FUNCTION "FC_GRP_84" : VOID
TITLE =GROUP =84
{ S7_language := '9(1) Angielski (Stany Zjednoczone)  11.01.2022  09:45:15' }
VERSION : 0.1


VAR_TEMP
  CL : "UDT_CABINET";	//CABINET LOCAL
  CR : "UDT_CABINET";	//CABINET REMOTE
  RelError : BOOL ;	//ERROR RELEASE
  RelErrorCL : BOOL ;	//ERROR RELEASE FROM CABINET LOCAL
  RelErrorCR : BOOL ;	//ERROR RELEASE FROM CABINET REMOTE
  RelControl : BOOL ;	//CONTROL RELEASE
  RelControlCL : BOOL ;	//CONTROL RELEASE FROM CABINET LOCAL
  RelControlCR : BOOL ;	//CONTROL RELEASE FROM CABINET REMOTE
  ErrorConfirm : BOOL ;	//ERROR CONFIRM
  AutoOn : BOOL ;	//AUTOMATIC ON
  AutoOff : BOOL ;	//AUTOMATIC OFF
  LAMP_ON : BOOL ;
  FLOW_METER_PE : BOOL ;
  Value_Offset : REAL ;	//VALUE OFFSET
END_VAR
BEGIN
NETWORK
TITLE =GLOBAL SIGNALS

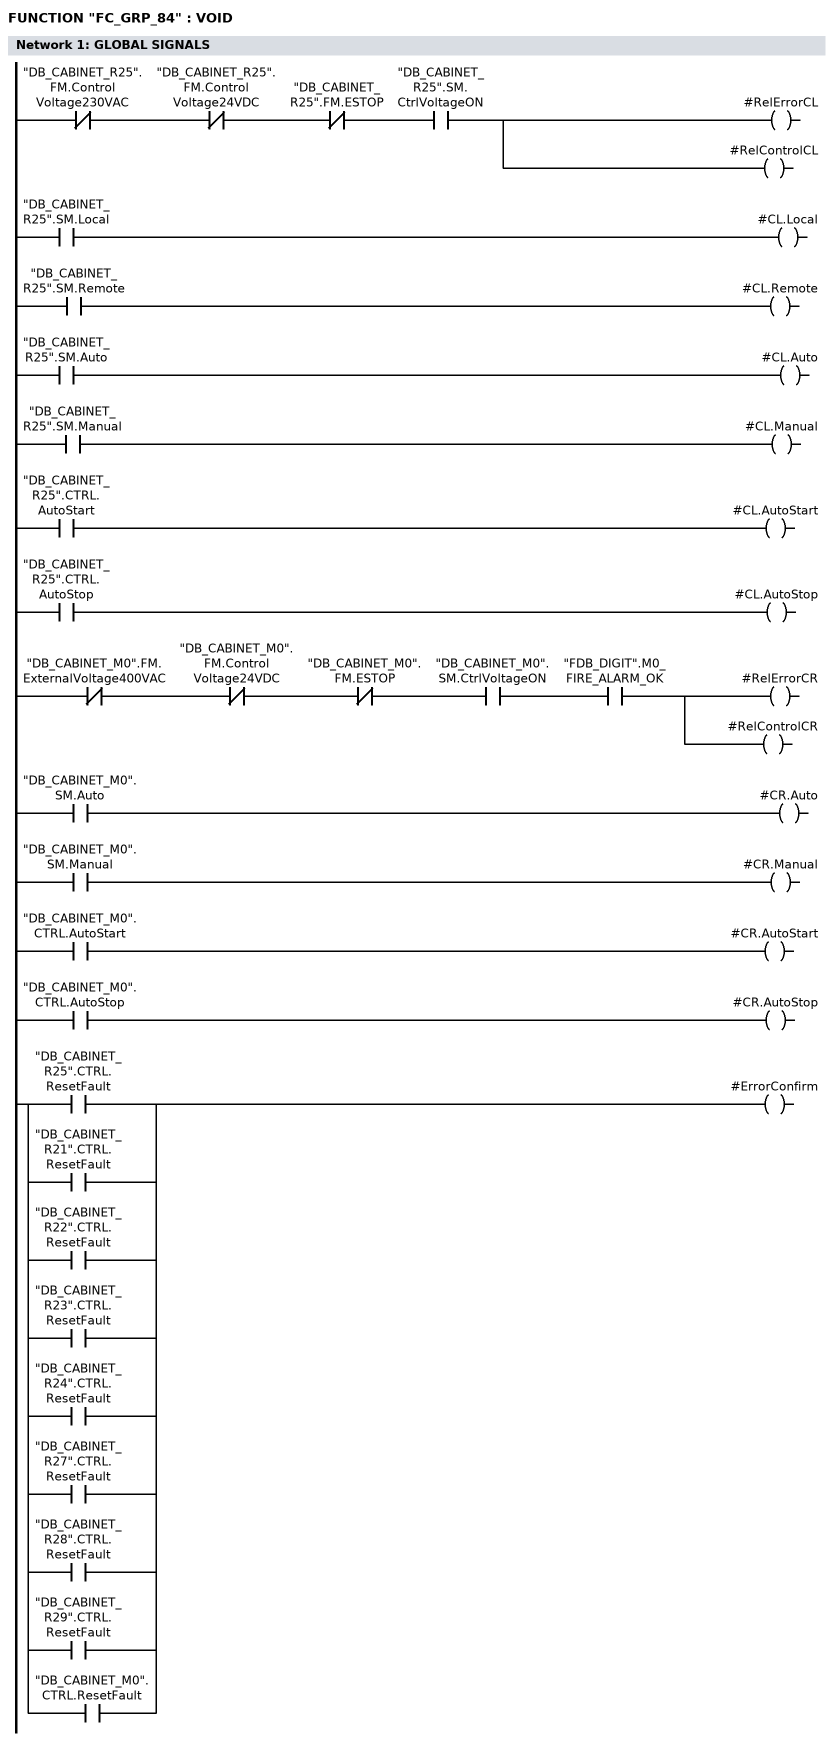
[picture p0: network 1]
// LOCAL
      UN    "DB_CABINET_R25".FM.ControlVoltage230VAC;
      UN    "DB_CABINET_R25".FM.ControlVoltage24VDC;
//      UN    "DB_CABINET_R25".FM.ControlVoltage230VAC_MS
      UN    "DB_CABINET_R25".FM.ESTOP;
      U     "DB_CABINET_R25".SM.CtrlVoltageON;
      =     #RelErrorCL;
      =     #RelControlCL;

      U     "DB_CABINET_R25".SM.Local;
      =     #CL.Local;
      U     "DB_CABINET_R25".SM.Remote;
      =     #CL.Remote;
      U     "DB_CABINET_R25".SM.Auto;
      =     #CL.Auto;
      U     "DB_CABINET_R25".SM.Manual;
      =     #CL.Manual;
      U     "DB_CABINET_R25".CTRL.AutoStart;
      =     #CL.AutoStart;
      U     "DB_CABINET_R25".CTRL.AutoStop;
      =     #CL.AutoStop;

// REMOTE
      UN    "DB_CABINET_M0".FM.ExternalVoltage400VAC;
      UN    "DB_CABINET_M0".FM.ControlVoltage24VDC;
//      UN    "DB_CABINET_M0".FM.ControlVoltage230VAC_MS
      UN    "DB_CABINET_M0".FM.ESTOP;
      U     "DB_CABINET_M0".SM.CtrlVoltageON;
      U     "FDB_DIGIT".M0_FIRE_ALARM_OK;
      =     #RelErrorCR;
      =     #RelControlCR;

      U     "DB_CABINET_M0".SM.Auto;
      =     #CR.Auto;
      U     "DB_CABINET_M0".SM.Manual;
      =     #CR.Manual;
      U     "DB_CABINET_M0".CTRL.AutoStart;
      =     #CR.AutoStart;
      U     "DB_CABINET_M0".CTRL.AutoStop;
      =     #CR.AutoStop;

      U     "DB_CABINET_R25".CTRL.ResetFault;
      O     "DB_CABINET_R21".CTRL.ResetFault;
      O     "DB_CABINET_R22".CTRL.ResetFault;
      O     "DB_CABINET_R23".CTRL.ResetFault;
      O     "DB_CABINET_R24".CTRL.ResetFault;
      O     "DB_CABINET_R27".CTRL.ResetFault;
      O     "DB_CABINET_R28".CTRL.ResetFault;
      O     "DB_CABINET_R29".CTRL.ResetFault;
      O     "DB_CABINET_M0".CTRL.ResetFault;
      =     #ErrorConfirm;

NETWORK
TITLE ==84DOO07-S1F ACCESS DOOR ERROR

      U(    ;
      U(    ;
      O     #ErrorConfirm;
      O     "R25-84DOO07+07TG1-S1:14";
      )     ;
      R     "DB_DIGIT".FM.G84_DOO07;
      U     "FDB_DIGIT".R25_84DOO07_OK;
      =     "DB_DIGIT".SM.G84_DOO07;
      U     "DB_DIGIT".SM.G84_DOO07;
      NOT   ;
      U     #RelErrorCL;
      U     #RelErrorCR;
      S     "DB_DIGIT".FM.G84_DOO07;
      U     "DB_DIGIT".FM.G84_DOO07;
      )     ;
      U     "DURATION_1";
      =     "R25-84DOO07+07TG1-H1:x1";
NETWORK
TITLE ==84FLA11-M1 RELEASE CONTROL/ERROR

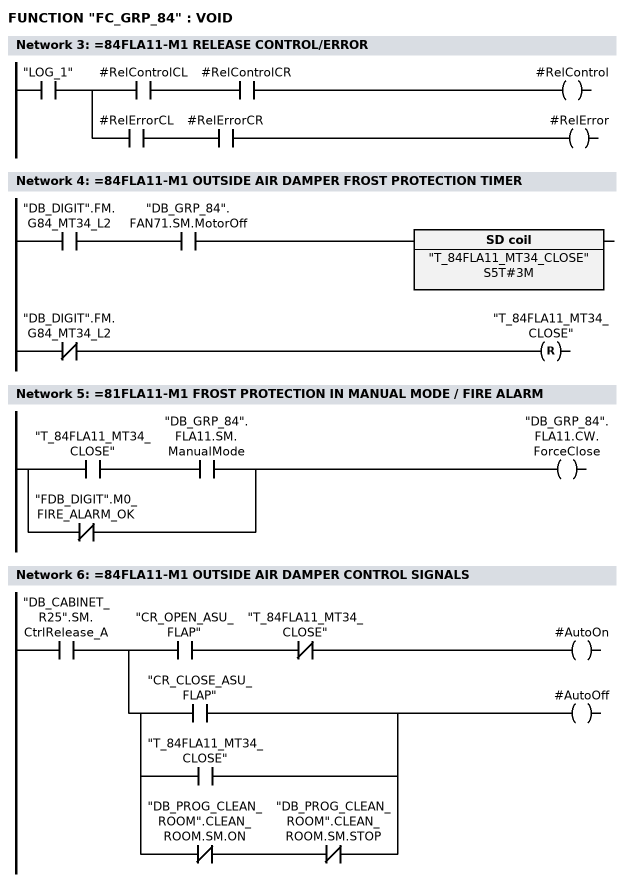
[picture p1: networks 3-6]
      U     "LOG_1";
      =     L     10.0;
      U     L     10.0;
      U     #RelControlCL;
      U     #RelControlCR;
      =     #RelControl;
      U     L     10.0;
      U     #RelErrorCL;
      U     #RelErrorCR;
      =     #RelError;
NETWORK
TITLE ==84FLA11-M1 OUTSIDE AIR DAMPER FROST PROTECTION TIMER

      U     "DB_DIGIT".FM.G84_MT34_L2;
      U     "DB_GRP_84".FAN71.SM.MotorOff;
      L     S5T#3M;
      SE    "T_84FLA11_MT34_CLOSE";
      UN    "DB_DIGIT".FM.G84_MT34_L2;
      R     "T_84FLA11_MT34_CLOSE";
      NOP   0;
      NOP   0;
      NOP   0;
NETWORK
TITLE ==81FLA11-M1 FROST PROTECTION IN MANUAL MODE / FIRE ALARM

      U     "T_84FLA11_MT34_CLOSE";
      U     "DB_GRP_84".FLA11.SM.ManualMode;
      ON    "FDB_DIGIT".M0_FIRE_ALARM_OK;
      =     "DB_GRP_84".FLA11.CW.ForceClose;
NETWORK
TITLE ==84FLA11-M1 OUTSIDE AIR DAMPER CONTROL SIGNALS

      U     "DB_CABINET_R25".SM.CtrlRelease_A;
      =     L     10.0;
      U     L     10.0;
      U     "CR_OPEN_ASU_FLAP";
      UN    "T_84FLA11_MT34_CLOSE";
      =     #AutoOn;
      U     L     10.0;
      U(    ;
      O     "CR_CLOSE_ASU_FLAP";
      O     "T_84FLA11_MT34_CLOSE";
      O     ;
      UN    "DB_PROG_CLEAN_ROOM".CLEAN_ROOM.SM.ON;
      UN    "DB_PROG_CLEAN_ROOM".CLEAN_ROOM.SM.STOP;
      )     ;
      =     #AutoOff;
NETWORK
TITLE ==84FLA11-M1 OUTSIDE AIR DAMPER

      U     #RelControl;
      =     L     10.0;
      BLD   103;
      U     #RelError;
      =     L     10.1;
      BLD   103;
      U     #AutoOn;
      =     L     10.2;
      BLD   103;
      U     #AutoOff;
      =     L     10.3;
      BLD   103;
      U     "LOG_1";
      =     L     10.4;
      BLD   103;
      U(    ;
      U     "R25-84FLA11+X-S1c:4";
      L     S5T#10S;
      SE    "T_84FLA11_LS_O";
      NOP   0;
      NOP   0;
      NOP   0;
      U     "T_84FLA11_LS_O";
      )     ;
      =     L     10.5;
      BLD   103;
      U(    ;
      U     "R25-84FLA11+X-S2c:4";
      L     S5T#10S;
      SE    "T_84FLA11_LS_C";
      NOP   0;
      NOP   0;
      NOP   0;
      U     "T_84FLA11_LS_C";
      )     ;
      =     L     10.6;
      BLD   103;
      U     #ErrorConfirm;
      =     L     10.7;
      BLD   103;
      CALL "FC_FLAP" (
           REL_CONTROL              := L     10.0,
           REL_ERROR                := L     10.1,
           CL                       := #CL,
           CR                       := #CR,
           AUTO_OPEN                := L     10.2,
           AUTO_CLOSE               := L     10.3,
           FUSE                     := L     10.4,
           LS_OPEN                  := L     10.5,
           LS_CLOSE                 := L     10.6,
           ERROR_CONFIRM            := L     10.7,
           MAX_RUNTIME              := 280,
           OPEN                     := "R25-84FLA11+X-M1:2",
           CLOSE                    := "R25-84FLA11+X-M1:3",
           DDB                      := "DB_GRP_84".FLA11);
      NOP   0;
NETWORK
TITLE ==84FTR20-B33 FILTER PRESSURE MONITORING

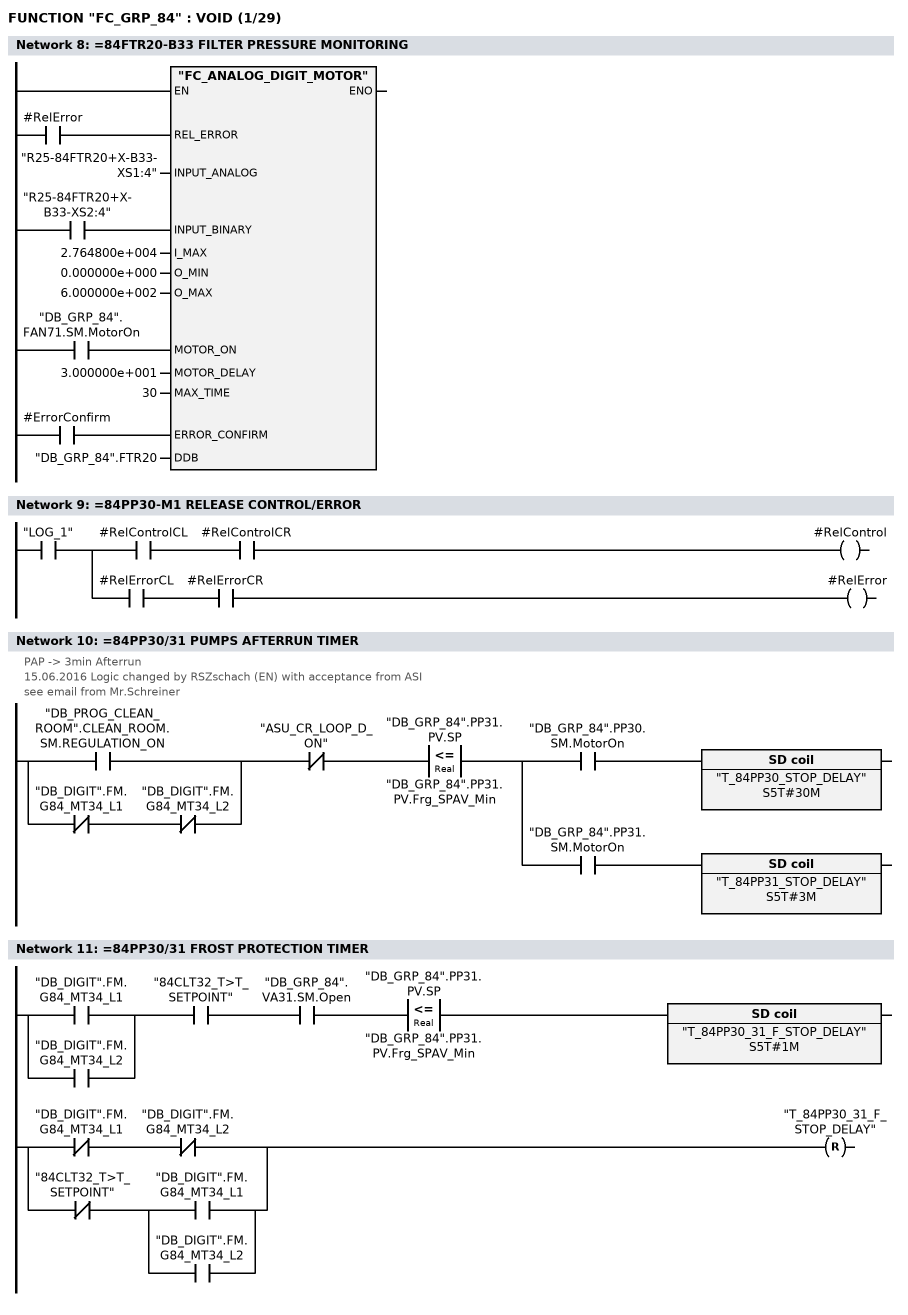
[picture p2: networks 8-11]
      U     #RelError;
      =     L     10.0;
      BLD   103;
      U     "R25-84FTR20+X-B33-XS2:4";
      =     L     10.1;
      BLD   103;
      U     "DB_GRP_84".FAN71.SM.MotorOn;
      =     L     10.2;
      BLD   103;
      U     #ErrorConfirm;
      =     L     10.3;
      BLD   103;
      CALL "FC_ANALOG_DIGIT_MOTOR" (
           REL_ERROR                := L     10.0,
           INPUT_ANALOG             := "R25-84FTR20+X-B33-XS1:4",
           INPUT_BINARY             := L     10.1,
           I_MAX                    := 2.764800e+004,
           O_MIN                    := 0.000000e+000,
           O_MAX                    := 6.000000e+002,
           MOTOR_ON                 := L     10.2,
           MOTOR_DELAY              := 3.000000e+001,
           MAX_TIME                 := 30,
           ERROR_CONFIRM            := L     10.3,
           DDB                      := "DB_GRP_84".FTR20);
      NOP   0;
NETWORK
TITLE ==84PP30-M1 RELEASE CONTROL/ERROR

      U     "LOG_1";
      =     L     10.0;
      U     L     10.0;
      U     #RelControlCL;
      U     #RelControlCR;
      =     #RelControl;
      U     L     10.0;
      U     #RelErrorCL;
      U     #RelErrorCR;
      =     #RelError;
NETWORK
TITLE ==84PP30/31 PUMPS AFTERRUN TIMER
//PAP -> 3min Afterrun
//
//15.06.2016 Logic changed by RSZschach (EN) with acceptance from ASI
//see email from Mr.Schreiner
      U(    ;
      O     "DB_PROG_CLEAN_ROOM".CLEAN_ROOM.SM.REGULATION_ON;
      O     ;
      UN    "DB_DIGIT".FM.G84_MT34_L1;
      UN    "DB_DIGIT".FM.G84_MT34_L2;
      )     ;
      UN    "ASU_CR_LOOP_D_ON";
      U(    ;
      L     "DB_GRP_84".PP31.PV.SP;
      L     "DB_GRP_84".PP31.PV.Frg_SPAV_Min;
      <=R   ;
      )     ;
      =     L     10.0;
      U     L     10.0;
      U     "DB_GRP_84".PP30.SM.MotorOn;
      L     S5T#30M;
      SE    "T_84PP30_STOP_DELAY";
      NOP   0;
      NOP   0;
      NOP   0;
      NOP   0;
      U     L     10.0;
      U     "DB_GRP_84".PP31.SM.MotorOn;
      L     S5T#3M;
      SE    "T_84PP31_STOP_DELAY";
      NOP   0;
      NOP   0;
      NOP   0;
      NOP   0;
NETWORK
TITLE ==84PP30/31 FROST PROTECTION TIMER

      U(    ;
      O     "DB_DIGIT".FM.G84_MT34_L1;
      O     "DB_DIGIT".FM.G84_MT34_L2;
      )     ;
      U     "84CLT32_T>T_SETPOINT";
      U     "DB_GRP_84".VA31.SM.Open;
      U(    ;
      L     "DB_GRP_84".PP31.PV.SP;
      L     "DB_GRP_84".PP31.PV.Frg_SPAV_Min;
      <=R   ;
      )     ;
      L     S5T#1M;
      SE    "T_84PP30_31_F_STOP_DELAY";
      U(    ;
      UN    "DB_DIGIT".FM.G84_MT34_L1;
      UN    "DB_DIGIT".FM.G84_MT34_L2;
      O     ;
      UN    "84CLT32_T>T_SETPOINT";
      U(    ;
      O     "DB_DIGIT".FM.G84_MT34_L1;
      O     "DB_DIGIT".FM.G84_MT34_L2;
      )     ;
      )     ;
      R     "T_84PP30_31_F_STOP_DELAY";
      NOP   0;
      NOP   0;
      NOP   0;
NETWORK
TITLE ==84PP30-M1 PREHEATING CIRCULATION PUMP CONTROL SIGNALS

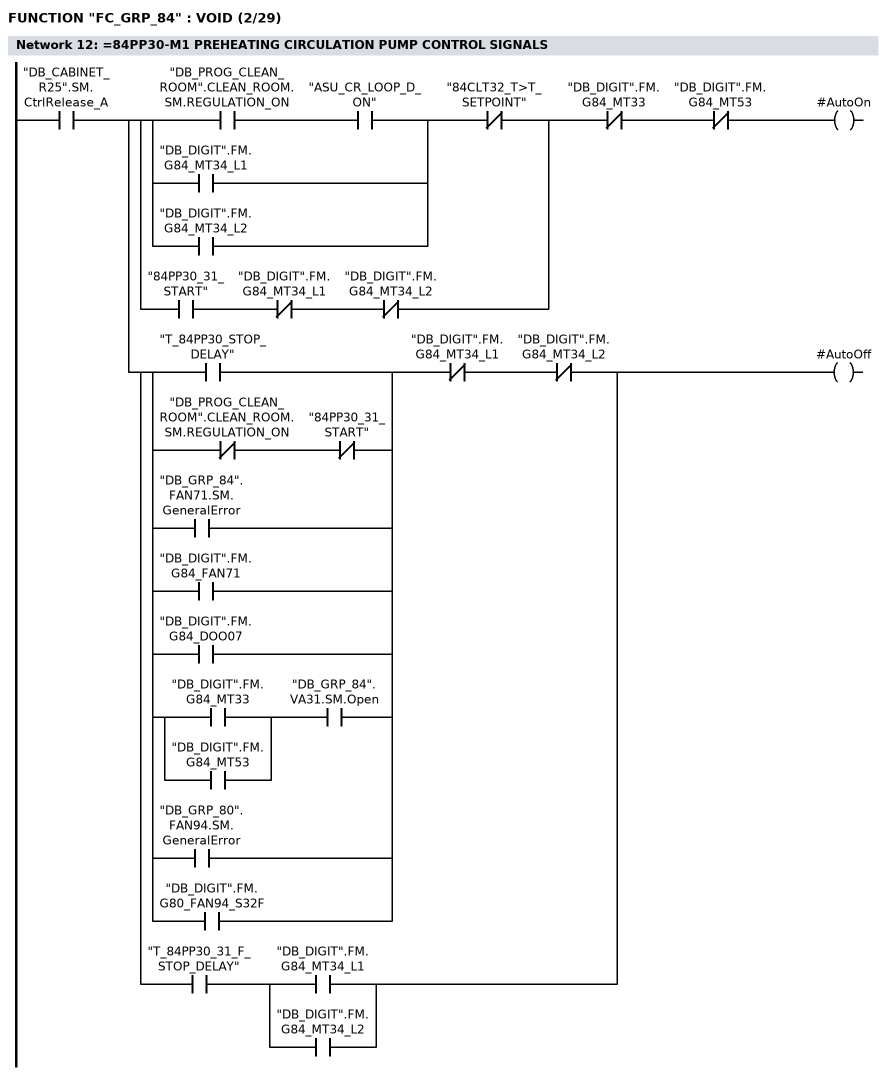
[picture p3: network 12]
      U     "DB_CABINET_R25".SM.CtrlRelease_A;
      =     L     10.0;
      U     L     10.0;
      U(    ;
      U(    ;
      U     "DB_PROG_CLEAN_ROOM".CLEAN_ROOM.SM.REGULATION_ON;
      U     "ASU_CR_LOOP_D_ON";
      O     "DB_DIGIT".FM.G84_MT34_L1;
      O     "DB_DIGIT".FM.G84_MT34_L2;
      )     ;
      UN    "84CLT32_T>T_SETPOINT";
      O     ;
      U     "84PP30_31_START";
      UN    "DB_DIGIT".FM.G84_MT34_L1;
      UN    "DB_DIGIT".FM.G84_MT34_L2;
      )     ;
      UN    "DB_DIGIT".FM.G84_MT33;
      UN    "DB_DIGIT".FM.G84_MT53;
      =     #AutoOn;
      U     L     10.0;
      U(    ;
      U(    ;
      O     "T_84PP30_STOP_DELAY";
      O     ;
      UN    "DB_PROG_CLEAN_ROOM".CLEAN_ROOM.SM.REGULATION_ON;
      UN    "84PP30_31_START";
      O     "DB_GRP_84".FAN71.SM.GeneralError;
      O     "DB_DIGIT".FM.G84_FAN71;
      O     "DB_DIGIT".FM.G84_DOO07;
      O     ;
      U(    ;
      O     "DB_DIGIT".FM.G84_MT33;
      O     "DB_DIGIT".FM.G84_MT53;
      )     ;
      U     "DB_GRP_84".VA31.SM.Open;
      O     "DB_GRP_80".FAN94.SM.GeneralError;
      O     "DB_DIGIT".FM.G80_FAN94_S32F;
      )     ;
      UN    "DB_DIGIT".FM.G84_MT34_L1;
      UN    "DB_DIGIT".FM.G84_MT34_L2;
      O     ;
      U     "T_84PP30_31_F_STOP_DELAY";
      U(    ;
      O     "DB_DIGIT".FM.G84_MT34_L1;
      O     "DB_DIGIT".FM.G84_MT34_L2;
      )     ;
      )     ;
      =     #AutoOff;
NETWORK
TITLE ==84PP30-M1 PREHEATING CIRCULATION PUMP

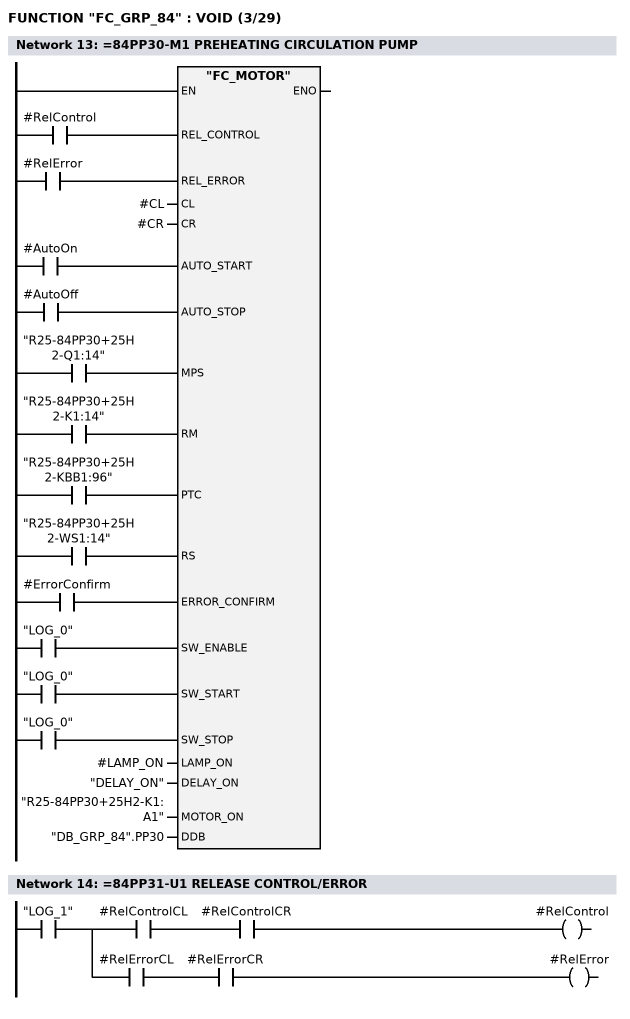
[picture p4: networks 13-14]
      U     #RelControl;
      =     L     10.0;
      BLD   103;
      U     #RelError;
      =     L     10.1;
      BLD   103;
      U     #AutoOn;
      =     L     10.2;
      BLD   103;
      U     #AutoOff;
      =     L     10.3;
      BLD   103;
      U     "R25-84PP30+25H2-Q1:14";
      =     L     10.4;
      BLD   103;
      U     "R25-84PP30+25H2-K1:14";
      =     L     10.5;
      BLD   103;
      U     "R25-84PP30+25H2-KBB1:96";
      =     L     10.6;
      BLD   103;
      U     "R25-84PP30+25H2-WS1:14";
      =     L     10.7;
      BLD   103;
      U     #ErrorConfirm;
      =     L     11.0;
      BLD   103;
      U     "LOG_0";
      =     L     11.1;
      BLD   103;
      U     "LOG_0";
      =     L     11.2;
      BLD   103;
      U     "LOG_0";
      =     L     11.3;
      BLD   103;
      CALL "FC_MOTOR" (
           REL_CONTROL              := L     10.0,
           REL_ERROR                := L     10.1,
           CL                       := #CL,
           CR                       := #CR,
           AUTO_START               := L     10.2,
           AUTO_STOP                := L     10.3,
           MPS                      := L     10.4,
           RM                       := L     10.5,
           PTC                      := L     10.6,
           RS                       := L     10.7,
           ERROR_CONFIRM            := L     11.0,
           SW_ENABLE                := L     11.1,
           SW_START                 := L     11.2,
           SW_STOP                  := L     11.3,
           LAMP_ON                  := #LAMP_ON,
           DELAY_ON                 := "DELAY_ON",
           MOTOR_ON                 := "R25-84PP30+25H2-K1:A1",
           DDB                      := "DB_GRP_84".PP30);
      NOP   0;
NETWORK
TITLE ==84PP31-U1 RELEASE CONTROL/ERROR

      U     "LOG_1";
      =     L     10.0;
      U     L     10.0;
      U     #RelControlCL;
      U     #RelControlCR;
      =     #RelControl;
      U     L     10.0;
      U     #RelErrorCL;
      U     #RelErrorCR;
      =     #RelError;
NETWORK
TITLE ==84PP31-U1 PREHEATING PUMP CONTROL SIGNALS

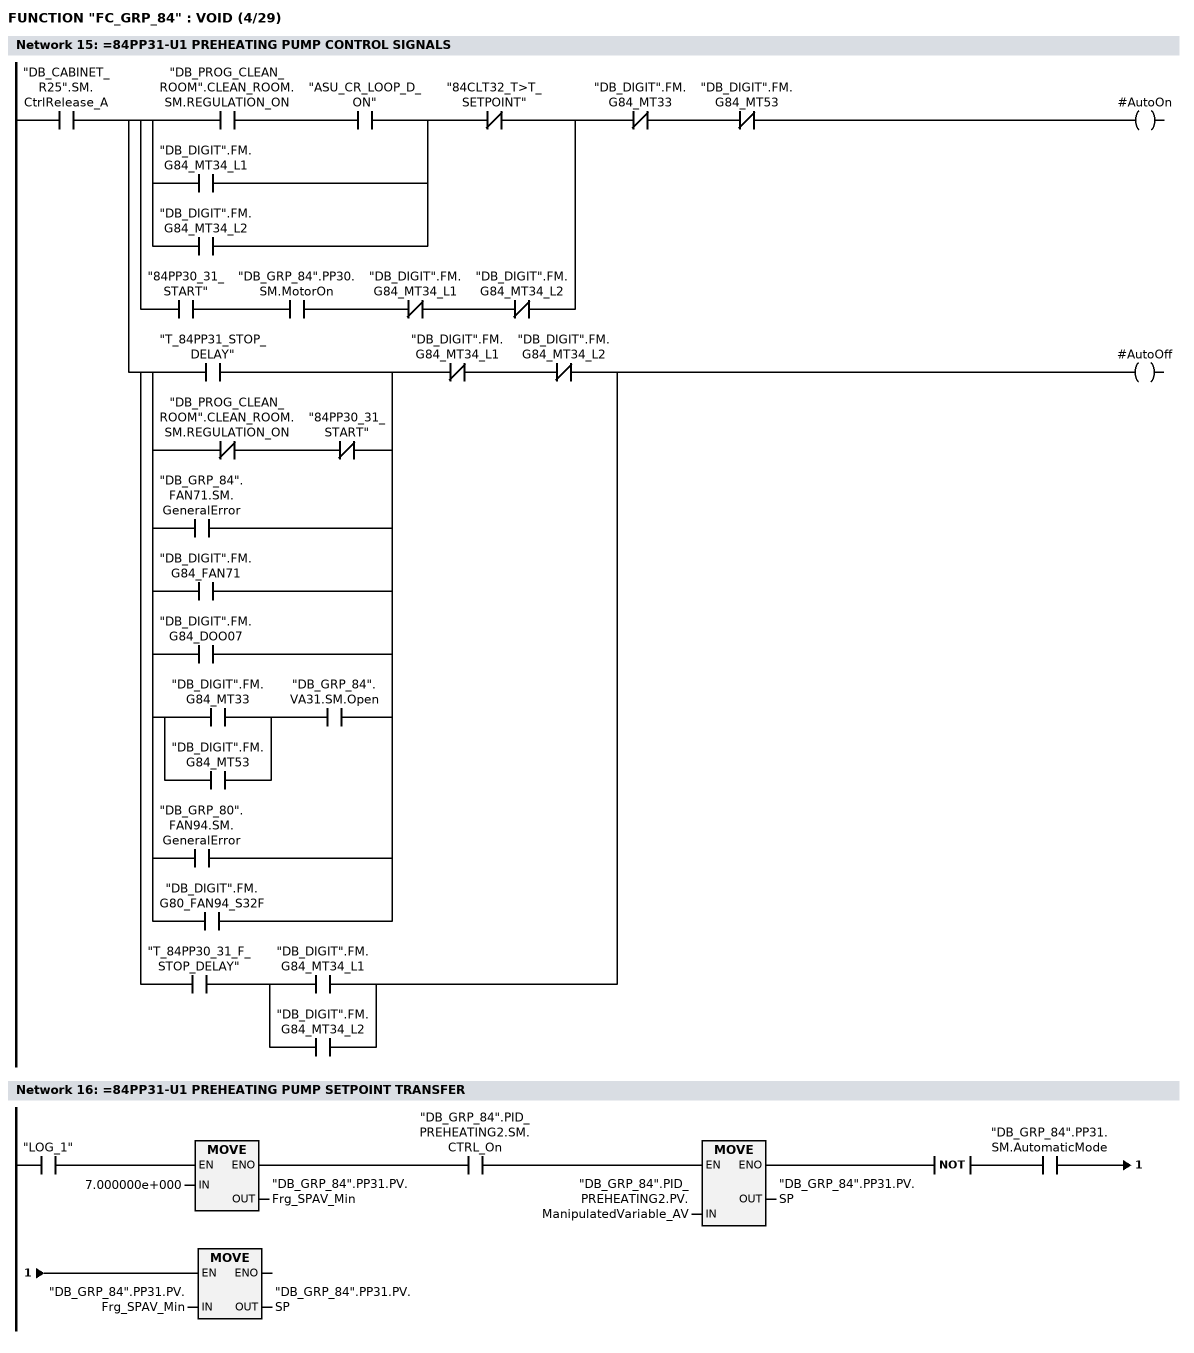
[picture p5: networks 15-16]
      U     "DB_CABINET_R25".SM.CtrlRelease_A;
      =     L     10.0;
      U     L     10.0;
      U(    ;
      U(    ;
      U     "DB_PROG_CLEAN_ROOM".CLEAN_ROOM.SM.REGULATION_ON;
      U     "ASU_CR_LOOP_D_ON";
      O     "DB_DIGIT".FM.G84_MT34_L1;
      O     "DB_DIGIT".FM.G84_MT34_L2;
      )     ;
      UN    "84CLT32_T>T_SETPOINT";
      O     ;
      U     "84PP30_31_START";
      U     "DB_GRP_84".PP30.SM.MotorOn;
      UN    "DB_DIGIT".FM.G84_MT34_L1;
      UN    "DB_DIGIT".FM.G84_MT34_L2;
      )     ;
      UN    "DB_DIGIT".FM.G84_MT33;
      UN    "DB_DIGIT".FM.G84_MT53;
      =     #AutoOn;
      U     L     10.0;
      U(    ;
      U(    ;
      O     "T_84PP31_STOP_DELAY";
      O     ;
      UN    "DB_PROG_CLEAN_ROOM".CLEAN_ROOM.SM.REGULATION_ON;
      UN    "84PP30_31_START";
      O     "DB_GRP_84".FAN71.SM.GeneralError;
      O     "DB_DIGIT".FM.G84_FAN71;
      O     "DB_DIGIT".FM.G84_DOO07;
      O     ;
      U(    ;
      O     "DB_DIGIT".FM.G84_MT33;
      O     "DB_DIGIT".FM.G84_MT53;
      )     ;
      U     "DB_GRP_84".VA31.SM.Open;
      O     "DB_GRP_80".FAN94.SM.GeneralError;
      O     "DB_DIGIT".FM.G80_FAN94_S32F;
      )     ;
      UN    "DB_DIGIT".FM.G84_MT34_L1;
      UN    "DB_DIGIT".FM.G84_MT34_L2;
      O     ;
      U     "T_84PP30_31_F_STOP_DELAY";
      U(    ;
      O     "DB_DIGIT".FM.G84_MT34_L1;
      O     "DB_DIGIT".FM.G84_MT34_L2;
      )     ;
      )     ;
      =     #AutoOff;
NETWORK
TITLE ==84PP31-U1 PREHEATING PUMP SETPOINT TRANSFER

      U(    ;
      U(    ;
      U     "LOG_1";
      SPBNB _001;
      L     7.000000e+000;
      T     "DB_GRP_84".PP31.PV.Frg_SPAV_Min;
      SET   ;
      SAVE  ;
      CLR   ;
_001: U     BIE;
      )     ;
      U     "DB_GRP_84".PID_PREHEATING2.SM.CTRL_On;
      SPBNB _002;
      L     "DB_GRP_84".PID_PREHEATING2.PV.ManipulatedVariable_AV;
      T     "DB_GRP_84".PP31.PV.SP;
      SET   ;
      SAVE  ;
      CLR   ;
_002: U     BIE;
      )     ;
      NOT   ;
      U     "DB_GRP_84".PP31.SM.AutomaticMode;
      SPBNB _003;
      L     "DB_GRP_84".PP31.PV.Frg_SPAV_Min;
      T     "DB_GRP_84".PP31.PV.SP;
_003: NOP   0;
NETWORK
TITLE ==84PP31-U1 PREHEATING PUMP

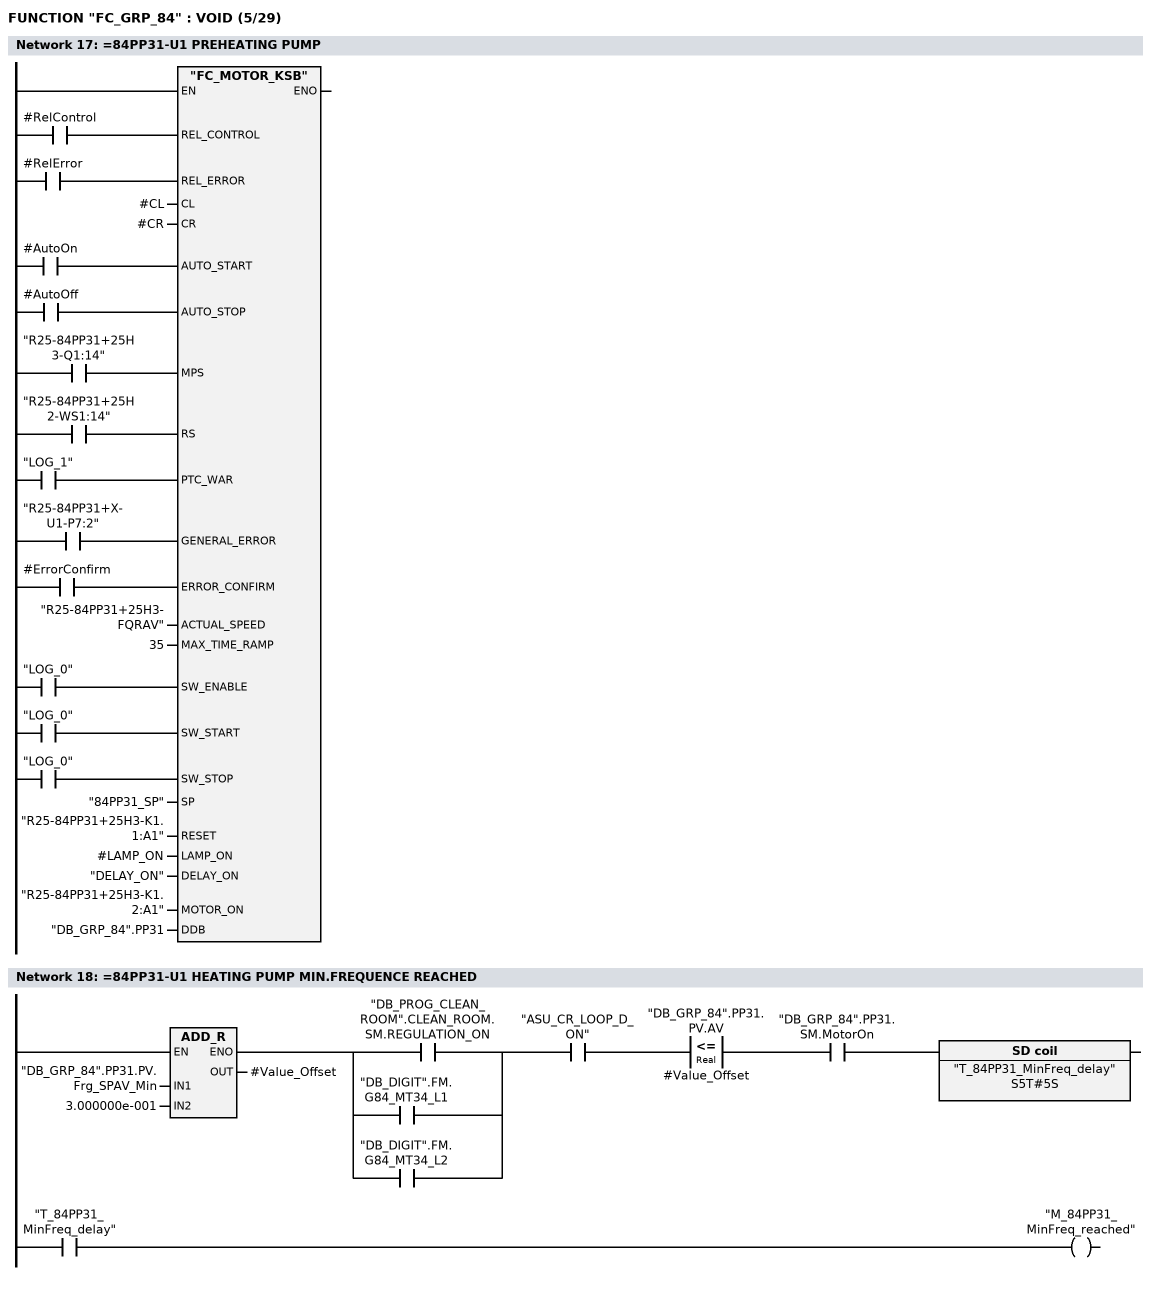
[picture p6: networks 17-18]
      U     #RelControl;
      =     L     10.0;
      BLD   103;
      U     #RelError;
      =     L     10.1;
      BLD   103;
      U     #AutoOn;
      =     L     10.2;
      BLD   103;
      U     #AutoOff;
      =     L     10.3;
      BLD   103;
      U     "R25-84PP31+25H3-Q1:14";
      =     L     10.4;
      BLD   103;
      U     "R25-84PP31+25H2-WS1:14";
      =     L     10.5;
      BLD   103;
      U     "LOG_1";
      =     L     10.6;
      BLD   103;
      U     "R25-84PP31+X-U1-P7:2";
      =     L     10.7;
      BLD   103;
      U     #ErrorConfirm;
      =     L     11.0;
      BLD   103;
      U     "LOG_0";
      =     L     11.1;
      BLD   103;
      U     "LOG_0";
      =     L     11.2;
      BLD   103;
      U     "LOG_0";
      =     L     11.3;
      BLD   103;
      CALL "FC_MOTOR_KSB" (
           REL_CONTROL              := L     10.0,
           REL_ERROR                := L     10.1,
           CL                       := #CL,
           CR                       := #CR,
           AUTO_START               := L     10.2,
           AUTO_STOP                := L     10.3,
           MPS                      := L     10.4,
           RS                       := L     10.5,
           PTC_WAR                  := L     10.6,
           GENERAL_ERROR            := L     10.7,
           ERROR_CONFIRM            := L     11.0,
           ACTUAL_SPEED             := "R25-84PP31+25H3-FQRAV",
           MAX_TIME_RAMP            := 35,
           SW_ENABLE                := L     11.1,
           SW_START                 := L     11.2,
           SW_STOP                  := L     11.3,
           SP                       := "84PP31_SP",
           RESET                    := "R25-84PP31+25H3-K1.1:A1",
           LAMP_ON                  := #LAMP_ON,
           DELAY_ON                 := "DELAY_ON",
           MOTOR_ON                 := "R25-84PP31+25H3-K1.2:A1",
           DDB                      := "DB_GRP_84".PP31);
      NOP   0;
NETWORK
TITLE ==84PP31-U1 HEATING PUMP MIN.FREQUENCE REACHED

      U(    ;
      L     "DB_GRP_84".PP31.PV.Frg_SPAV_Min;
      L     3.000000e-001;
      +R    ;
      T     #Value_Offset;
      UN    OV;
      SAVE  ;
      CLR   ;
      U     BIE;
      )     ;
      U(    ;
      O     "DB_PROG_CLEAN_ROOM".CLEAN_ROOM.SM.REGULATION_ON;
      O     "DB_DIGIT".FM.G84_MT34_L1;
      O     "DB_DIGIT".FM.G84_MT34_L2;
      )     ;
      U     "ASU_CR_LOOP_D_ON";
      U(    ;
      L     "DB_GRP_84".PP31.PV.AV;
      L     #Value_Offset;
      <=R   ;
      )     ;
      U     "DB_GRP_84".PP31.SM.MotorOn;
      L     S5T#5S;
      SE    "T_84PP31_MinFreq_delay";
      NOP   0;
      NOP   0;
      NOP   0;
      U     "T_84PP31_MinFreq_delay";
      =     "M_84PP31_MinFreq_reached";
NETWORK
TITLE ==84VA31-M1 RELEASE CONTROL/ERROR

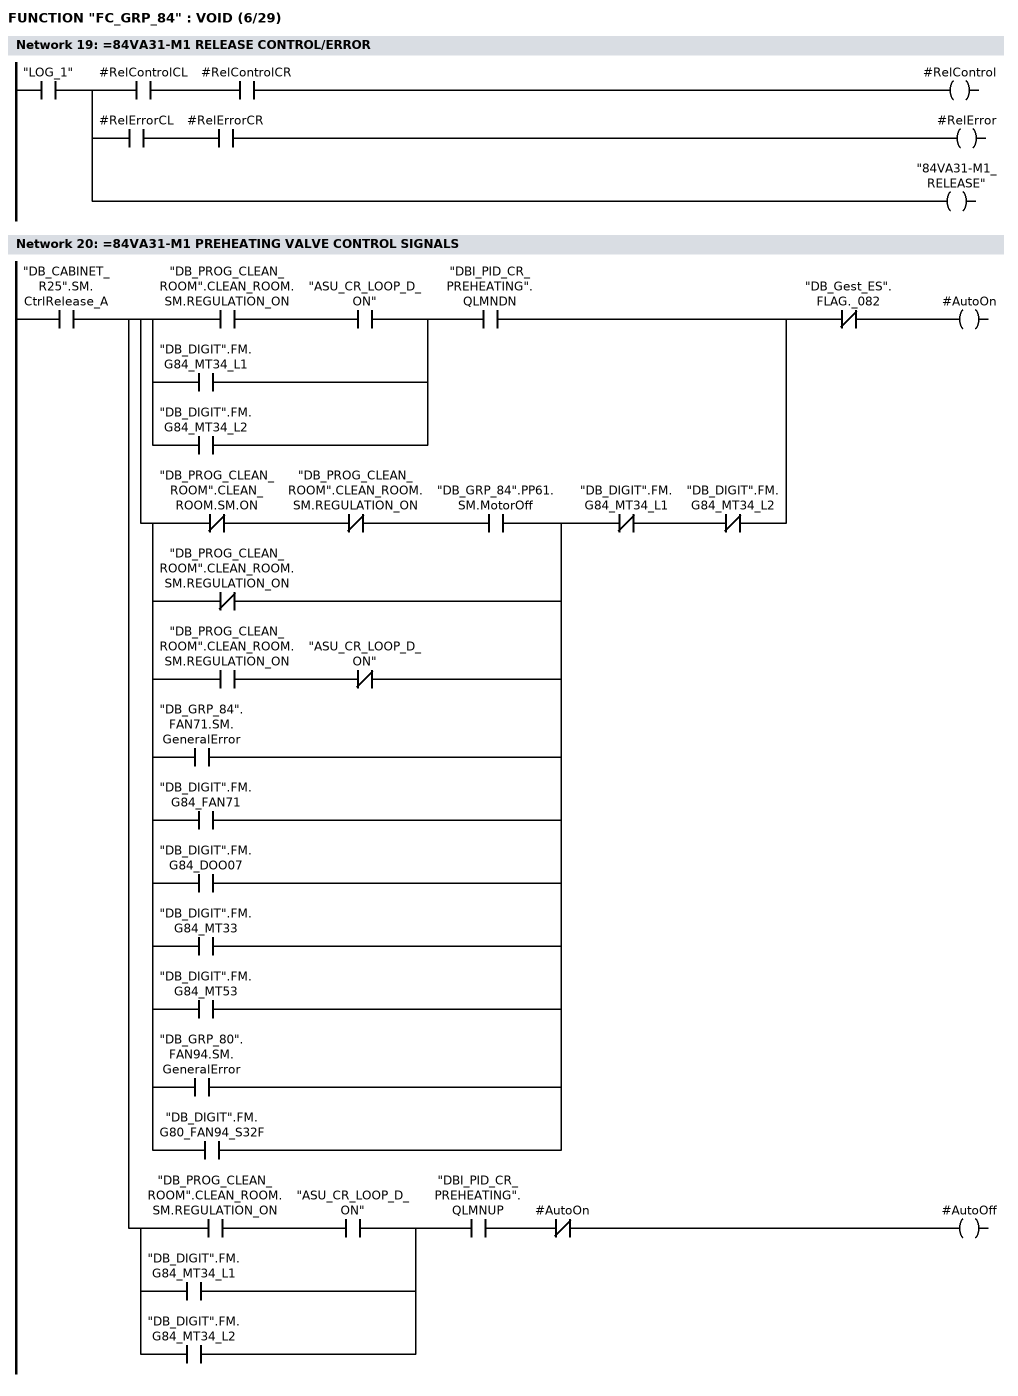
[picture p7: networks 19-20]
      U     "LOG_1";
      =     L     10.0;
      U     L     10.0;
      U     #RelControlCL;
      U     #RelControlCR;
      =     #RelControl;
      U     L     10.0;
      U     #RelErrorCL;
      U     #RelErrorCR;
      =     #RelError;
      U     L     10.0;
      BLD   102;
      =     "84VA31-M1_RELEASE";
NETWORK
TITLE ==84VA31-M1 PREHEATING VALVE CONTROL SIGNALS

      U     "DB_CABINET_R25".SM.CtrlRelease_A;
      =     L     10.0;
      U     L     10.0;
      U(    ;
      U(    ;
      U     "DB_PROG_CLEAN_ROOM".CLEAN_ROOM.SM.REGULATION_ON;
      U     "ASU_CR_LOOP_D_ON";
      O     "DB_DIGIT".FM.G84_MT34_L1;
      O     "DB_DIGIT".FM.G84_MT34_L2;
      )     ;
      U     "DBI_PID_CR_PREHEATING".QLMNDN;
      O     ;
      U(    ;
      UN    "DB_PROG_CLEAN_ROOM".CLEAN_ROOM.SM.ON;
      UN    "DB_PROG_CLEAN_ROOM".CLEAN_ROOM.SM.REGULATION_ON;
      U     "DB_GRP_84".PP61.SM.MotorOff;
      ON    "DB_PROG_CLEAN_ROOM".CLEAN_ROOM.SM.REGULATION_ON;
      O     ;
      U     "DB_PROG_CLEAN_ROOM".CLEAN_ROOM.SM.REGULATION_ON;
      UN    "ASU_CR_LOOP_D_ON";
      O     "DB_GRP_84".FAN71.SM.GeneralError;
      O     "DB_DIGIT".FM.G84_FAN71;
      O     "DB_DIGIT".FM.G84_DOO07;
      O     "DB_DIGIT".FM.G84_MT33;
      O     "DB_DIGIT".FM.G84_MT53;
      O     "DB_GRP_80".FAN94.SM.GeneralError;
      O     "DB_DIGIT".FM.G80_FAN94_S32F;
      )     ;
      UN    "DB_DIGIT".FM.G84_MT34_L1;
      UN    "DB_DIGIT".FM.G84_MT34_L2;
      )     ;
      UN    "DB_Gest_ES".FLAG._082;
      =     #AutoOn;
      U     L     10.0;
      U(    ;
      U     "DB_PROG_CLEAN_ROOM".CLEAN_ROOM.SM.REGULATION_ON;
      U     "ASU_CR_LOOP_D_ON";
      O     "DB_DIGIT".FM.G84_MT34_L1;
      O     "DB_DIGIT".FM.G84_MT34_L2;
      )     ;
      U     "DBI_PID_CR_PREHEATING".QLMNUP;
      UN    #AutoOn;
      =     #AutoOff;
NETWORK
TITLE ==84VA31-M1 FORCE OPENING

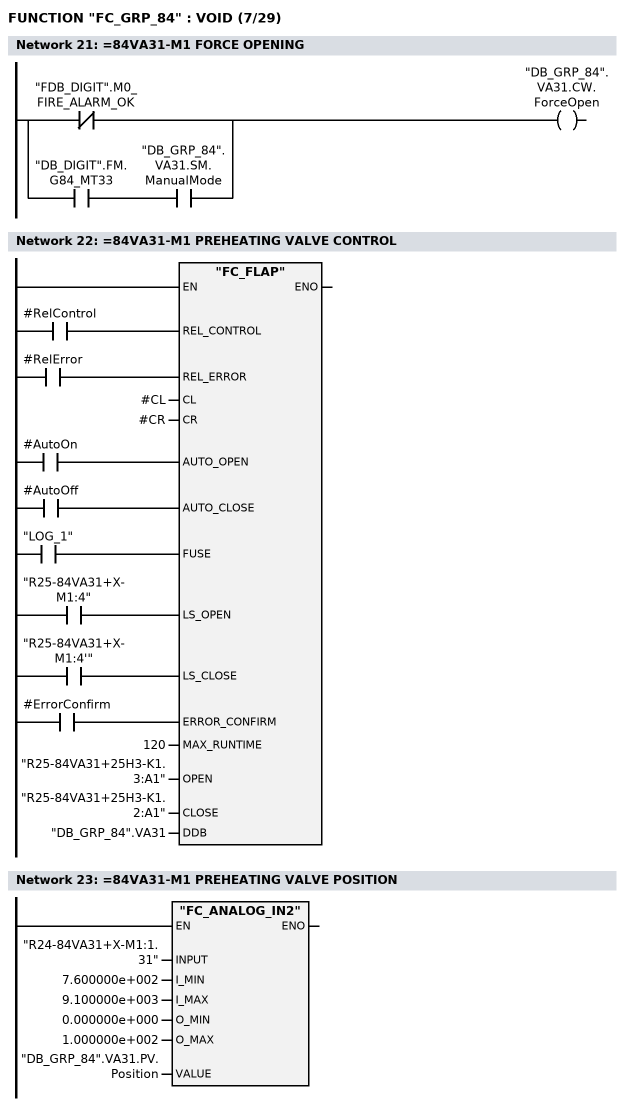
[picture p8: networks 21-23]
      ON    "FDB_DIGIT".M0_FIRE_ALARM_OK;
      O     ;
      U     "DB_DIGIT".FM.G84_MT33;
      U     "DB_GRP_84".VA31.SM.ManualMode;
      =     "DB_GRP_84".VA31.CW.ForceOpen;
NETWORK
TITLE ==84VA31-M1 PREHEATING VALVE CONTROL

      U     #RelControl;
      =     L     10.0;
      BLD   103;
      U     #RelError;
      =     L     10.1;
      BLD   103;
      U     #AutoOn;
      =     L     10.2;
      BLD   103;
      U     #AutoOff;
      =     L     10.3;
      BLD   103;
      U     "LOG_1";
      =     L     10.4;
      BLD   103;
      U     "R25-84VA31+X-M1:4";
      =     L     10.5;
      BLD   103;
      U     "R25-84VA31+X-M1:4'";
      =     L     10.6;
      BLD   103;
      U     #ErrorConfirm;
      =     L     10.7;
      BLD   103;
      CALL "FC_FLAP" (
           REL_CONTROL              := L     10.0,
           REL_ERROR                := L     10.1,
           CL                       := #CL,
           CR                       := #CR,
           AUTO_OPEN                := L     10.2,
           AUTO_CLOSE               := L     10.3,
           FUSE                     := L     10.4,
           LS_OPEN                  := L     10.5,
           LS_CLOSE                 := L     10.6,
           ERROR_CONFIRM            := L     10.7,
           MAX_RUNTIME              := 120,
           OPEN                     := "R25-84VA31+25H3-K1.3:A1",
           CLOSE                    := "R25-84VA31+25H3-K1.2:A1",
           DDB                      := "DB_GRP_84".VA31);
      NOP   0;
NETWORK
TITLE ==84VA31-M1 PREHEATING VALVE POSITION

      CALL "FC_ANALOG_IN2" (
           INPUT                    := "R24-84VA31+X-M1:1.31",
           I_MIN                    := 7.600000e+002,
           I_MAX                    := 9.100000e+003,
           O_MIN                    := 0.000000e+000,
           O_MAX                    := 1.000000e+002,
           VALUE                    := "DB_GRP_84".VA31.PV.Position);
      NOP   0;
NETWORK
TITLE =FORCE 84CLT32-B40N ERR. REL. IF WINDOW IS NOT REACHED AFTER TIME

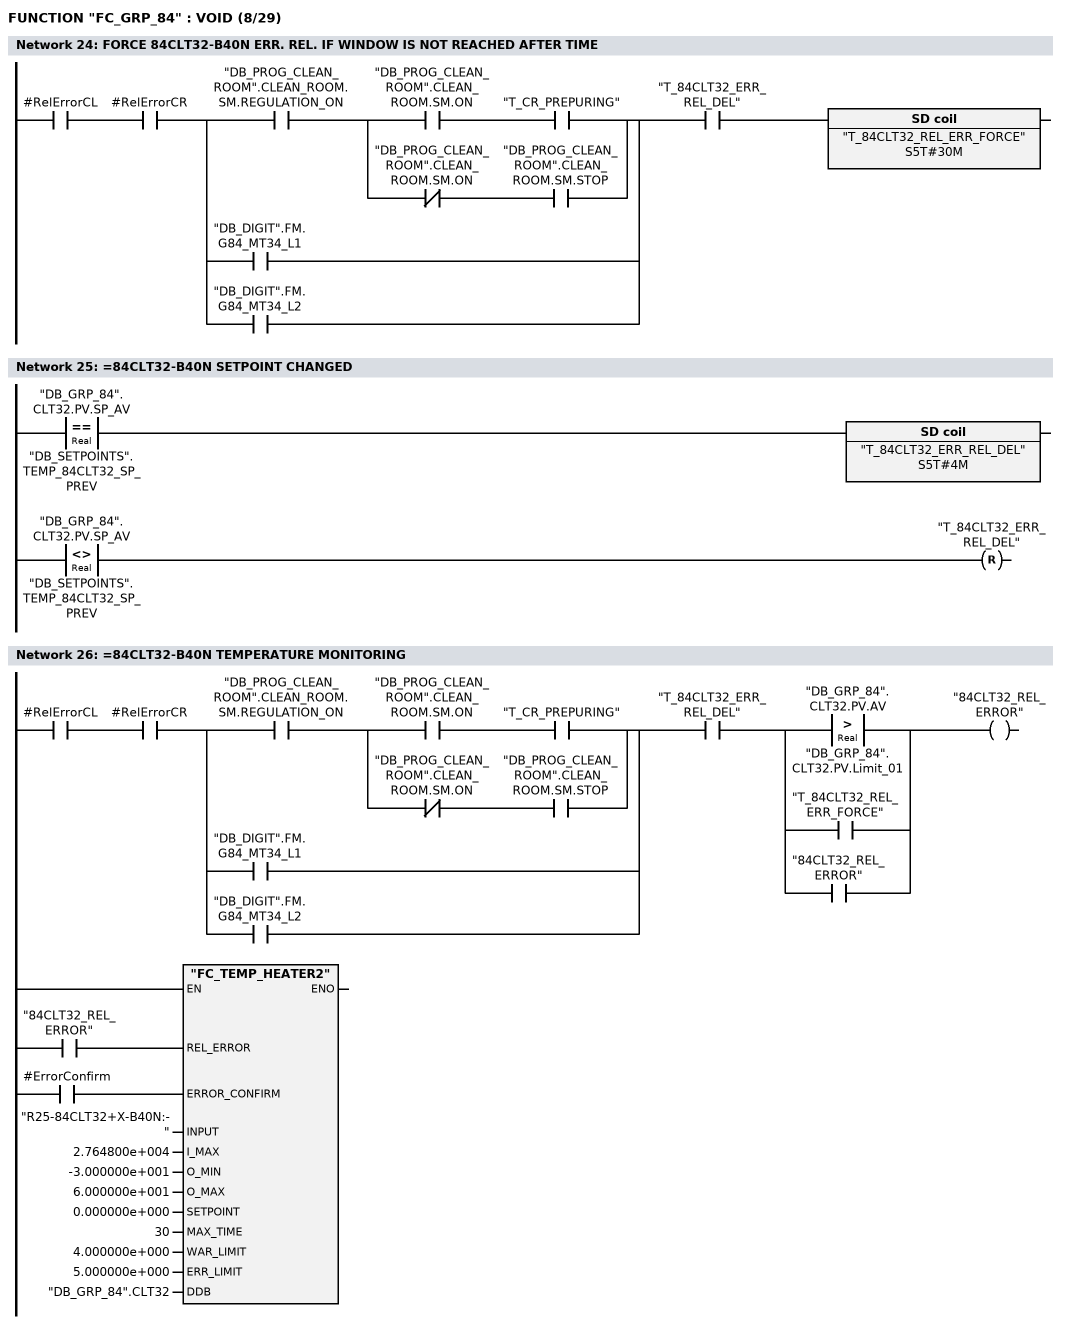
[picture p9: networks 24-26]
      U     #RelErrorCL;
      U     #RelErrorCR;
      U(    ;
      U     "DB_PROG_CLEAN_ROOM".CLEAN_ROOM.SM.REGULATION_ON;
      U(    ;
      U     "DB_PROG_CLEAN_ROOM".CLEAN_ROOM.SM.ON;
      U     "T_CR_PREPURING";
      O     ;
      UN    "DB_PROG_CLEAN_ROOM".CLEAN_ROOM.SM.ON;
      U     "DB_PROG_CLEAN_ROOM".CLEAN_ROOM.SM.STOP;
      )     ;
      O     "DB_DIGIT".FM.G84_MT34_L1;
      O     "DB_DIGIT".FM.G84_MT34_L2;
      )     ;
      U     "T_84CLT32_ERR_REL_DEL";
      L     S5T#30M;
      SE    "T_84CLT32_REL_ERR_FORCE";
      NOP   0;
      NOP   0;
      NOP   0;
      NOP   0;
NETWORK
TITLE ==84CLT32-B40N SETPOINT CHANGED

      U(    ;
      L     "DB_GRP_84".CLT32.PV.SP_AV;
      L     "DB_SETPOINTS".TEMP_84CLT32_SP_PREV;
      ==R   ;
      )     ;
      L     S5T#4M;
      SE    "T_84CLT32_ERR_REL_DEL";
      U(    ;
      L     "DB_GRP_84".CLT32.PV.SP_AV;
      L     "DB_SETPOINTS".TEMP_84CLT32_SP_PREV;
      <>R   ;
      )     ;
      R     "T_84CLT32_ERR_REL_DEL";
      NOP   0;
      NOP   0;
      NOP   0;
NETWORK
TITLE ==84CLT32-B40N TEMPERATURE MONITORING

      U     #RelErrorCL;
      U     #RelErrorCR;
      U(    ;
      U     "DB_PROG_CLEAN_ROOM".CLEAN_ROOM.SM.REGULATION_ON;
      U(    ;
      U     "DB_PROG_CLEAN_ROOM".CLEAN_ROOM.SM.ON;
      U     "T_CR_PREPURING";
      O     ;
      UN    "DB_PROG_CLEAN_ROOM".CLEAN_ROOM.SM.ON;
      U     "DB_PROG_CLEAN_ROOM".CLEAN_ROOM.SM.STOP;
      )     ;
      O     "DB_DIGIT".FM.G84_MT34_L1;
      O     "DB_DIGIT".FM.G84_MT34_L2;
      )     ;
      U     "T_84CLT32_ERR_REL_DEL";
      U(    ;
      O(    ;
      L     "DB_GRP_84".CLT32.PV.AV;
      L     "DB_GRP_84".CLT32.PV.Limit_01;
      >R    ;
      )     ;
      O     "T_84CLT32_REL_ERR_FORCE";
      O     "84CLT32_REL_ERROR";
      )     ;
      =     "84CLT32_REL_ERROR";
      U     "84CLT32_REL_ERROR";
      =     L     10.0;
      BLD   103;
      U     #ErrorConfirm;
      =     L     10.1;
      BLD   103;
      CALL "FC_TEMP_HEATER2" (
           REL_ERROR                := L     10.0,
           ERROR_CONFIRM            := L     10.1,
           INPUT                    := "R25-84CLT32+X-B40N:-",
           I_MAX                    := 2.764800e+004,
           O_MIN                    := -3.000000e+001,
           O_MAX                    := 6.000000e+001,
           SETPOINT                 := 0.000000e+000,
           MAX_TIME                 := 30,
           WAR_LIMIT                := 4.000000e+000,
           ERR_LIMIT                := 5.000000e+000,
           DDB                      := "DB_GRP_84".CLT32);
      NOP   0;
NETWORK
TITLE =CURRENT SETPOINT TO PREVIOUS SETPOINT

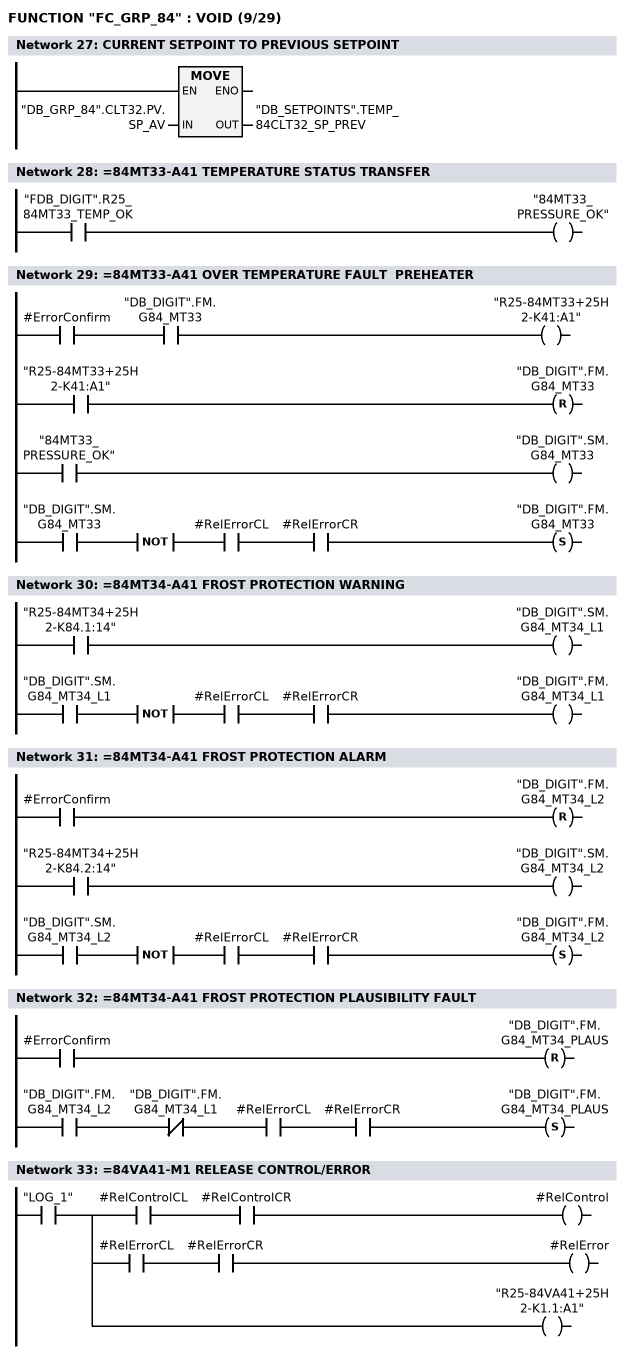
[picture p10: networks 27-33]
      L     "DB_GRP_84".CLT32.PV.SP_AV;
      T     "DB_SETPOINTS".TEMP_84CLT32_SP_PREV;
      NOP   0;
NETWORK
TITLE ==84MT33-A41 TEMPERATURE STATUS TRANSFER

      U     "FDB_DIGIT".R25_84MT33_TEMP_OK;
      =     "84MT33_PRESSURE_OK";
NETWORK
TITLE ==84MT33-A41 OVER TEMPERATURE FAULT  PREHEATER

      U     #ErrorConfirm;
      U     "DB_DIGIT".FM.G84_MT33;
      =     "R25-84MT33+25H2-K41:A1";
      U     "R25-84MT33+25H2-K41:A1";
      R     "DB_DIGIT".FM.G84_MT33;
      U     "84MT33_PRESSURE_OK";
      =     "DB_DIGIT".SM.G84_MT33;
      U     "DB_DIGIT".SM.G84_MT33;
      NOT   ;
      U     #RelErrorCL;
      U     #RelErrorCR;
      S     "DB_DIGIT".FM.G84_MT33;
      NOP   0;
NETWORK
TITLE ==84MT34-A41 FROST PROTECTION WARNING

      U     "R25-84MT34+25H2-K84.1:14";
      =     "DB_DIGIT".SM.G84_MT34_L1;
      U     "DB_DIGIT".SM.G84_MT34_L1;
      NOT   ;
      U     #RelErrorCL;
      U     #RelErrorCR;
      =     "DB_DIGIT".FM.G84_MT34_L1;
NETWORK
TITLE ==84MT34-A41 FROST PROTECTION ALARM

      U     #ErrorConfirm;
      R     "DB_DIGIT".FM.G84_MT34_L2;
      U     "R25-84MT34+25H2-K84.2:14";
      =     "DB_DIGIT".SM.G84_MT34_L2;
      U     "DB_DIGIT".SM.G84_MT34_L2;
      NOT   ;
      U     #RelErrorCL;
      U     #RelErrorCR;
      S     "DB_DIGIT".FM.G84_MT34_L2;
      NOP   0;
NETWORK
TITLE ==84MT34-A41 FROST PROTECTION PLAUSIBILITY FAULT

      U     #ErrorConfirm;
      R     "DB_DIGIT".FM.G84_MT34_PLAUS;
      U     "DB_DIGIT".FM.G84_MT34_L2;
      UN    "DB_DIGIT".FM.G84_MT34_L1;
      U     #RelErrorCL;
      U     #RelErrorCR;
      S     "DB_DIGIT".FM.G84_MT34_PLAUS;
      NOP   0;
NETWORK
TITLE ==84VA41-M1 RELEASE CONTROL/ERROR

      U     "LOG_1";
      =     L     10.0;
      U     L     10.0;
      U     #RelControlCL;
      U     #RelControlCR;
      =     #RelControl;
      U     L     10.0;
      U     #RelErrorCL;
      U     #RelErrorCR;
      =     #RelError;
      U     L     10.0;
      BLD   102;
      =     "R25-84VA41+25H2-K1.1:A1";
NETWORK
TITLE ==84VA41-M1 COOLING/DEHUMIDIFYING VALVE CONTROL SIGNALS
//"84CLT81_T>T_SP_COOL"
//
// U     "DB_CABINET_R25".SM.CtrlRelease_A
//      =     L      6.0
//      U     L      6.0
//      U     "DB_PROG_CLEAN_ROOM".CLEAN_ROOM.SM.REGULATION_ON
//      U(
//      UN    "DB_POWER_SAVING_MODE2".GENERAL.SM.CR_MODE_2_ON
//      U     "ASU_CR_LOOP_A_ON"
//      U(
//      O     "84CLT81_T>T_SP"
//      O     "84CLM82_R.H>R.H_SP"
//      )
//      O
//      U     "DB_POWER_SAVING_MODE2".GENERAL.SM.CR_MODE_2_ON
//      U(
//      O     "DB_POWER_SAVING_MODE2".MODE.CR_ASU_COOLING
//      O     "DB_POWER_SAVING_MODE2".MODE.CR_ASU_DEHUMIDIFYING
//      )
//      )
//      U(
//      ON    "ASU_CR_LOOP_B_ON"
//      O
//      U     "84CLT81_T>T_SP_COOL"
//      U     "ASU_CR_LOOP_B_ON"
//      U     "COMM_0"
//      )
//      U(
//      ON    "ASU_CR_LOOP_C_ON"
//      O
//      U     "84CLM82_R.H>R.H_SP_DEHUM"
//      U     "ASU_CR_LOOP_C_ON"
//      U     "COMM_0"
//      )
//      U(
//      O     "DBI_PID_CR_COOL".QLMNUP
//      O     "DBI_PID_CR_DEHUM".QLMNUP
//      )
//      =     #AutoOn
//      U     L      6.0
//      U(
//      U(
//      UN    "DB_POWER_SAVING_MODE2".GENERAL.SM.CR_MODE_2_ON
//      U     "ASU_CR_LOOP_A_ON"
//      O
//      U     "DB_POWER_SAVING_MODE2".GENERAL.SM.CR_MODE_2_ON
//      U(
//      O     "DB_POWER_SAVING_MODE2".MODE.CR_ASU_COOLING
//      O     "DB_POWER_SAVING_MODE2".MODE.CR_ASU_DEHUMIDIFYING
//      )
//      )
//      U     "LOG_1"
//      U(
//      O     "DBI_PID_CR_COOL".QLMNDN
//      O     "DBI_PID_CR_DEHUM".QLMNDN
//      )
//      O
//      UN    "DB_POWER_SAVING_MODE2".GENERAL.SM.CR_MODE_2_ON
//      UN    "ASU_CR_LOOP_A_ON"
//      O
//      U     "DB_POWER_SAVING_MODE2".GENERAL.SM.CR_MODE_2_ON
//      UN    "DB_POWER_SAVING_MODE2".MODE.CR_ASU_COOLING
//      UN    "DB_POWER_SAVING_MODE2".MODE.CR_ASU_DEHUMIDIFYING
//      ON    "DB_PROG_CLEAN_ROOM".CLEAN_ROOM.SM.REGULATION_ON
//      O     "DB_GRP_80".FAN94.SM.GeneralError
//      O     "DB_GRP_84".FAN71.SM.GeneralError
//      O     "DB_DIGIT".FM.G80_FAN94_S32F
//      O     "DB_DIGIT".FM.G84_FAN71
//      O     "DB_DIGIT".FM.G84_DOO07
//      )
//      =     #AutoOff
//
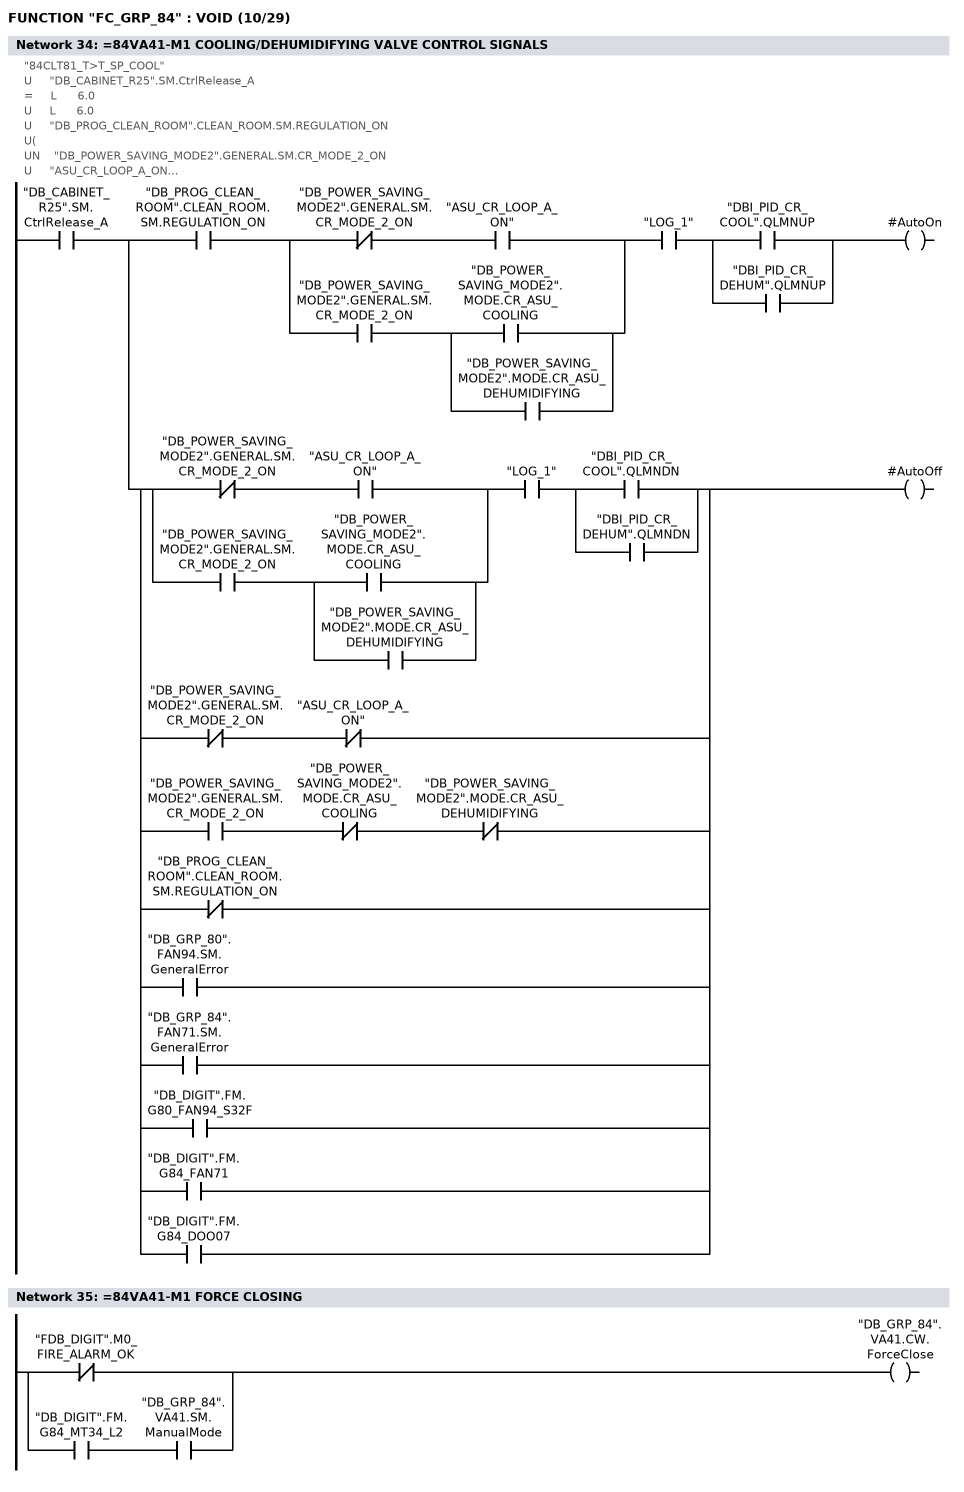
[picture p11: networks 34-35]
      U     "DB_CABINET_R25".SM.CtrlRelease_A;
      =     L     10.0;
      U     L     10.0;
      U     "DB_PROG_CLEAN_ROOM".CLEAN_ROOM.SM.REGULATION_ON;
      U(    ;
      UN    "DB_POWER_SAVING_MODE2".GENERAL.SM.CR_MODE_2_ON;
      U     "ASU_CR_LOOP_A_ON";
      O     ;
      U     "DB_POWER_SAVING_MODE2".GENERAL.SM.CR_MODE_2_ON;
      U(    ;
      O     "DB_POWER_SAVING_MODE2".MODE.CR_ASU_COOLING;
      O     "DB_POWER_SAVING_MODE2".MODE.CR_ASU_DEHUMIDIFYING;
      )     ;
      )     ;
      U     "LOG_1";
      U(    ;
      O     "DBI_PID_CR_COOL".QLMNUP;
      O     "DBI_PID_CR_DEHUM".QLMNUP;
      )     ;
      =     #AutoOn;
      U     L     10.0;
      U(    ;
      U(    ;
      UN    "DB_POWER_SAVING_MODE2".GENERAL.SM.CR_MODE_2_ON;
      U     "ASU_CR_LOOP_A_ON";
      O     ;
      U     "DB_POWER_SAVING_MODE2".GENERAL.SM.CR_MODE_2_ON;
      U(    ;
      O     "DB_POWER_SAVING_MODE2".MODE.CR_ASU_COOLING;
      O     "DB_POWER_SAVING_MODE2".MODE.CR_ASU_DEHUMIDIFYING;
      )     ;
      )     ;
      U     "LOG_1";
      U(    ;
      O     "DBI_PID_CR_COOL".QLMNDN;
      O     "DBI_PID_CR_DEHUM".QLMNDN;
      )     ;
      O     ;
      UN    "DB_POWER_SAVING_MODE2".GENERAL.SM.CR_MODE_2_ON;
      UN    "ASU_CR_LOOP_A_ON";
      O     ;
      U     "DB_POWER_SAVING_MODE2".GENERAL.SM.CR_MODE_2_ON;
      UN    "DB_POWER_SAVING_MODE2".MODE.CR_ASU_COOLING;
      UN    "DB_POWER_SAVING_MODE2".MODE.CR_ASU_DEHUMIDIFYING;
      ON    "DB_PROG_CLEAN_ROOM".CLEAN_ROOM.SM.REGULATION_ON;
      O     "DB_GRP_80".FAN94.SM.GeneralError;
      O     "DB_GRP_84".FAN71.SM.GeneralError;
      O     "DB_DIGIT".FM.G80_FAN94_S32F;
      O     "DB_DIGIT".FM.G84_FAN71;
      O     "DB_DIGIT".FM.G84_DOO07;
      )     ;
      =     #AutoOff;
NETWORK
TITLE ==84VA41-M1 FORCE CLOSING

      ON    "FDB_DIGIT".M0_FIRE_ALARM_OK;
      O     ;
      U     "DB_DIGIT".FM.G84_MT34_L2;
      U     "DB_GRP_84".VA41.SM.ManualMode;
      =     "DB_GRP_84".VA41.CW.ForceClose;
NETWORK
TITLE ==84VA41-M1 COOLING/DEHUMIDIFYING VALVE CONTROL

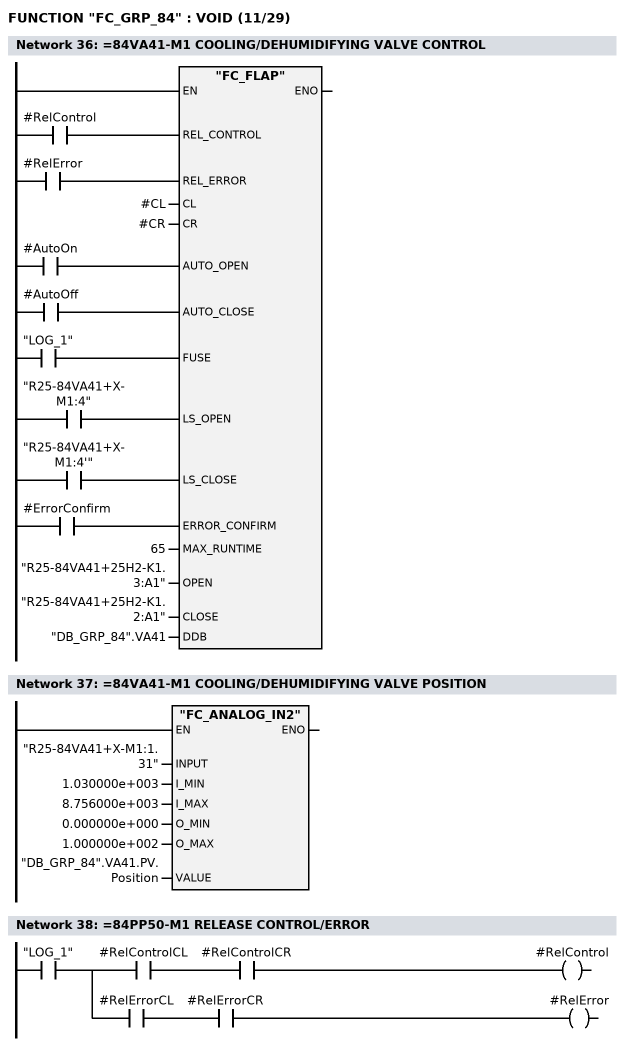
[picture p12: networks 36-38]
      U     #RelControl;
      =     L     10.0;
      BLD   103;
      U     #RelError;
      =     L     10.1;
      BLD   103;
      U     #AutoOn;
      =     L     10.2;
      BLD   103;
      U     #AutoOff;
      =     L     10.3;
      BLD   103;
      U     "LOG_1";
      =     L     10.4;
      BLD   103;
      U     "R25-84VA41+X-M1:4";
      =     L     10.5;
      BLD   103;
      U     "R25-84VA41+X-M1:4'";
      =     L     10.6;
      BLD   103;
      U     #ErrorConfirm;
      =     L     10.7;
      BLD   103;
      CALL "FC_FLAP" (
           REL_CONTROL              := L     10.0,
           REL_ERROR                := L     10.1,
           CL                       := #CL,
           CR                       := #CR,
           AUTO_OPEN                := L     10.2,
           AUTO_CLOSE               := L     10.3,
           FUSE                     := L     10.4,
           LS_OPEN                  := L     10.5,
           LS_CLOSE                 := L     10.6,
           ERROR_CONFIRM            := L     10.7,
           MAX_RUNTIME              := 65,
           OPEN                     := "R25-84VA41+25H2-K1.3:A1",
           CLOSE                    := "R25-84VA41+25H2-K1.2:A1",
           DDB                      := "DB_GRP_84".VA41);
      NOP   0;
NETWORK
TITLE ==84VA41-M1 COOLING/DEHUMIDIFYING VALVE POSITION

      CALL "FC_ANALOG_IN2" (
           INPUT                    := "R25-84VA41+X-M1:1.31",
           I_MIN                    := 1.030000e+003,
           I_MAX                    := 8.756000e+003,
           O_MIN                    := 0.000000e+000,
           O_MAX                    := 1.000000e+002,
           VALUE                    := "DB_GRP_84".VA41.PV.Position);
      NOP   0;
NETWORK
TITLE ==84PP50-M1 RELEASE CONTROL/ERROR

      U     "LOG_1";
      =     L     10.0;
      U     L     10.0;
      U     #RelControlCL;
      U     #RelControlCR;
      =     #RelControl;
      U     L     10.0;
      U     #RelErrorCL;
      U     #RelErrorCR;
      =     #RelError;
NETWORK
TITLE ==84PP50/51 PUMPS AFTERRUN TIMER
//PAP -> 3min Afterrun
//
//15.06.2016 Logic changed by RSZschach (EN) with acceptance from ASI
//see email from Mr.Schreiner
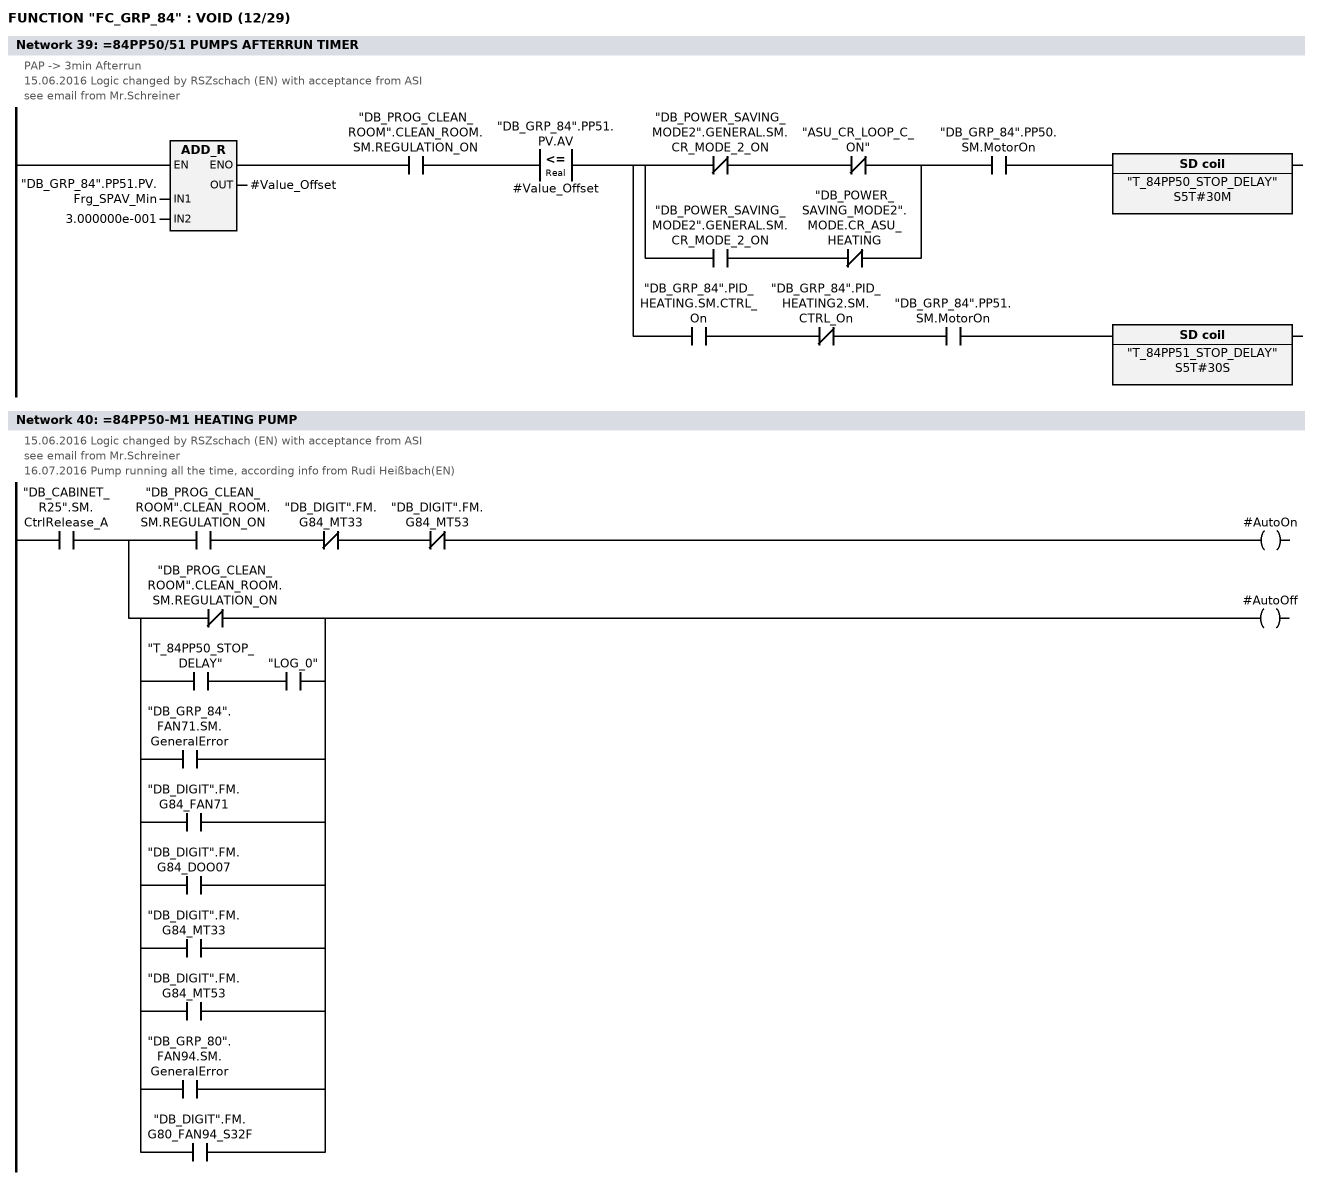
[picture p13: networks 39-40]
      U(    ;
      L     "DB_GRP_84".PP51.PV.Frg_SPAV_Min;
      L     3.000000e-001;
      +R    ;
      T     #Value_Offset;
      UN    OV;
      SAVE  ;
      CLR   ;
      U     BIE;
      )     ;
      U     "DB_PROG_CLEAN_ROOM".CLEAN_ROOM.SM.REGULATION_ON;
      U(    ;
      L     "DB_GRP_84".PP51.PV.AV;
      L     #Value_Offset;
      <=R   ;
      )     ;
      =     L     10.0;
      U     L     10.0;
      U(    ;
      UN    "DB_POWER_SAVING_MODE2".GENERAL.SM.CR_MODE_2_ON;
      UN    "ASU_CR_LOOP_C_ON";
      O     ;
      U     "DB_POWER_SAVING_MODE2".GENERAL.SM.CR_MODE_2_ON;
      UN    "DB_POWER_SAVING_MODE2".MODE.CR_ASU_HEATING;
      )     ;
      U     "DB_GRP_84".PP50.SM.MotorOn;
      L     S5T#30M;
      SE    "T_84PP50_STOP_DELAY";
      NOP   0;
      NOP   0;
      NOP   0;
      NOP   0;
      U     L     10.0;
      U     "DB_GRP_84".PID_HEATING.SM.CTRL_On;
      UN    "DB_GRP_84".PID_HEATING2.SM.CTRL_On;
      U     "DB_GRP_84".PP51.SM.MotorOn;
      L     S5T#30S;
      SE    "T_84PP51_STOP_DELAY";
      NOP   0;
      NOP   0;
      NOP   0;
      NOP   0;
NETWORK
TITLE ==84PP50-M1 HEATING PUMP
//15.06.2016 Logic changed by RSZschach (EN) with acceptance from ASI
//see email from Mr.Schreiner
//
//16.07.2016 Pump running all the time, according info from Rudi Heißbach(EN)
      U     "DB_CABINET_R25".SM.CtrlRelease_A;
      =     L     10.0;
      U     L     10.0;
      U     "DB_PROG_CLEAN_ROOM".CLEAN_ROOM.SM.REGULATION_ON;
      UN    "DB_DIGIT".FM.G84_MT33;
      UN    "DB_DIGIT".FM.G84_MT53;
      =     #AutoOn;
      U     L     10.0;
      U(    ;
      ON    "DB_PROG_CLEAN_ROOM".CLEAN_ROOM.SM.REGULATION_ON;
      O     ;
      U     "T_84PP50_STOP_DELAY";
      U     "LOG_0";
      O     "DB_GRP_84".FAN71.SM.GeneralError;
      O     "DB_DIGIT".FM.G84_FAN71;
      O     "DB_DIGIT".FM.G84_DOO07;
      O     "DB_DIGIT".FM.G84_MT33;
      O     "DB_DIGIT".FM.G84_MT53;
      O     "DB_GRP_80".FAN94.SM.GeneralError;
      O     "DB_DIGIT".FM.G80_FAN94_S32F;
      )     ;
      =     #AutoOff;
NETWORK
TITLE ==84PP50-M1 HEATING PUMP CONTROL

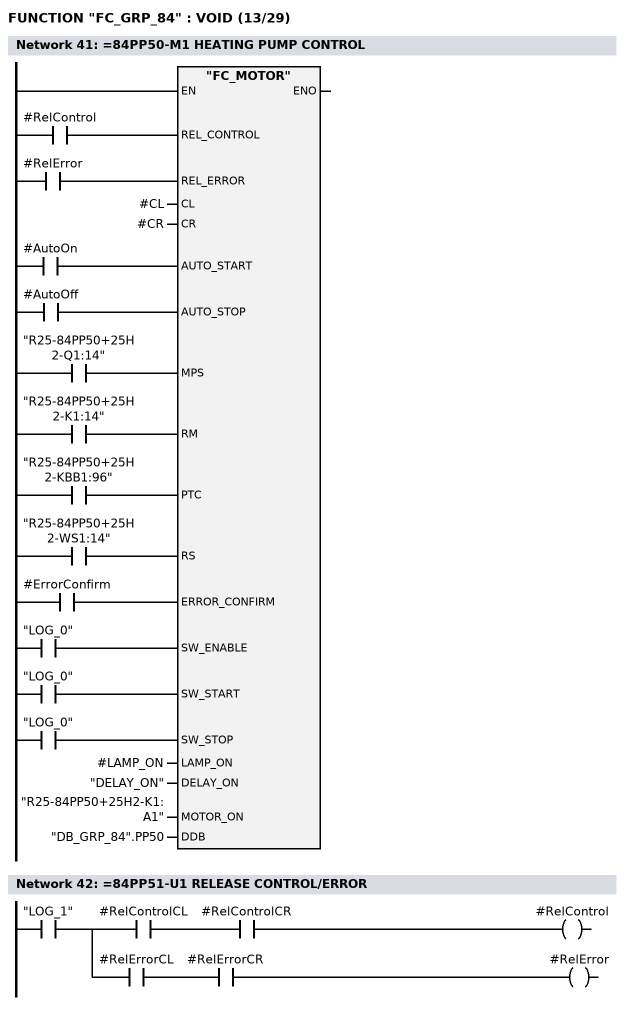
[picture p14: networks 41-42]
      U     #RelControl;
      =     L     10.0;
      BLD   103;
      U     #RelError;
      =     L     10.1;
      BLD   103;
      U     #AutoOn;
      =     L     10.2;
      BLD   103;
      U     #AutoOff;
      =     L     10.3;
      BLD   103;
      U     "R25-84PP50+25H2-Q1:14";
      =     L     10.4;
      BLD   103;
      U     "R25-84PP50+25H2-K1:14";
      =     L     10.5;
      BLD   103;
      U     "R25-84PP50+25H2-KBB1:96";
      =     L     10.6;
      BLD   103;
      U     "R25-84PP50+25H2-WS1:14";
      =     L     10.7;
      BLD   103;
      U     #ErrorConfirm;
      =     L     11.0;
      BLD   103;
      U     "LOG_0";
      =     L     11.1;
      BLD   103;
      U     "LOG_0";
      =     L     11.2;
      BLD   103;
      U     "LOG_0";
      =     L     11.3;
      BLD   103;
      CALL "FC_MOTOR" (
           REL_CONTROL              := L     10.0,
           REL_ERROR                := L     10.1,
           CL                       := #CL,
           CR                       := #CR,
           AUTO_START               := L     10.2,
           AUTO_STOP                := L     10.3,
           MPS                      := L     10.4,
           RM                       := L     10.5,
           PTC                      := L     10.6,
           RS                       := L     10.7,
           ERROR_CONFIRM            := L     11.0,
           SW_ENABLE                := L     11.1,
           SW_START                 := L     11.2,
           SW_STOP                  := L     11.3,
           LAMP_ON                  := #LAMP_ON,
           DELAY_ON                 := "DELAY_ON",
           MOTOR_ON                 := "R25-84PP50+25H2-K1:A1",
           DDB                      := "DB_GRP_84".PP50);
      NOP   0;
NETWORK
TITLE ==84PP51-U1 RELEASE CONTROL/ERROR

      U     "LOG_1";
      =     L     10.0;
      U     L     10.0;
      U     #RelControlCL;
      U     #RelControlCR;
      =     #RelControl;
      U     L     10.0;
      U     #RelErrorCL;
      U     #RelErrorCR;
      =     #RelError;
NETWORK
TITLE ==84PP51-U1 HEATING PUMP CONTROL SIGNALS
//15.06.2016 Logic changed by RSZschach (EN) with acceptance from ASI
//see email from Mr.Schreiner
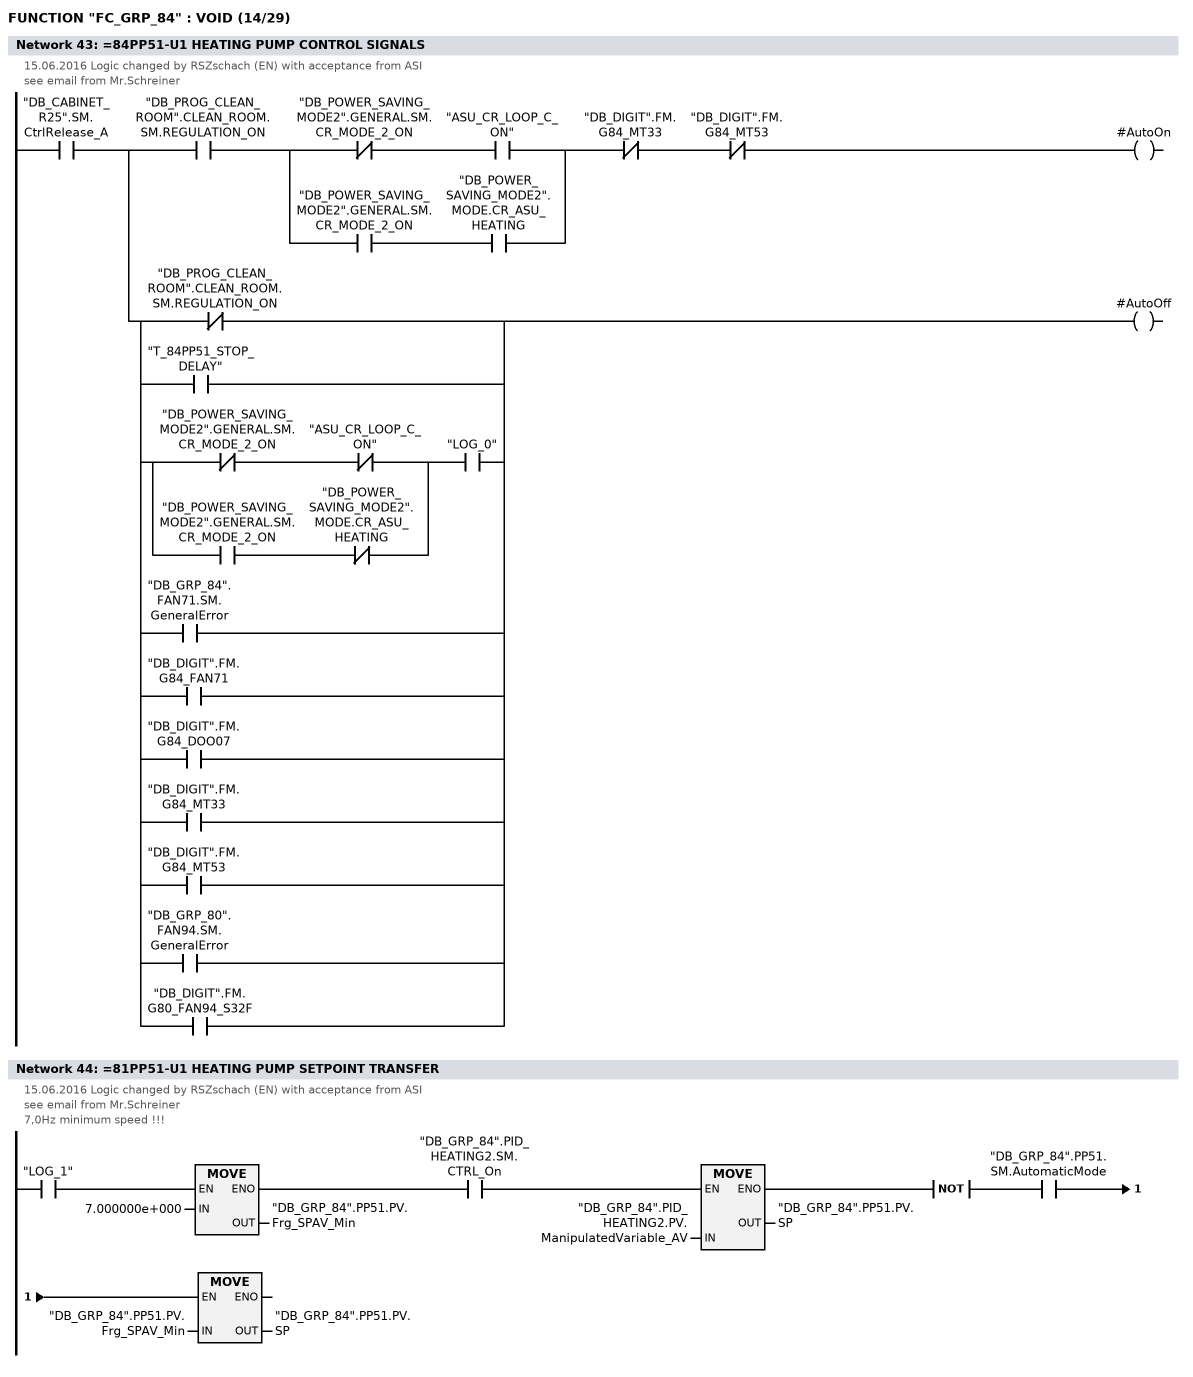
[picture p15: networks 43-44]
      U     "DB_CABINET_R25".SM.CtrlRelease_A;
      =     L     10.0;
      U     L     10.0;
      U     "DB_PROG_CLEAN_ROOM".CLEAN_ROOM.SM.REGULATION_ON;
      U(    ;
      UN    "DB_POWER_SAVING_MODE2".GENERAL.SM.CR_MODE_2_ON;
      U     "ASU_CR_LOOP_C_ON";
      O     ;
      U     "DB_POWER_SAVING_MODE2".GENERAL.SM.CR_MODE_2_ON;
      U     "DB_POWER_SAVING_MODE2".MODE.CR_ASU_HEATING;
      )     ;
      UN    "DB_DIGIT".FM.G84_MT33;
      UN    "DB_DIGIT".FM.G84_MT53;
      =     #AutoOn;
      U     L     10.0;
      U(    ;
      ON    "DB_PROG_CLEAN_ROOM".CLEAN_ROOM.SM.REGULATION_ON;
      O     "T_84PP51_STOP_DELAY";
      O     ;
      U(    ;
      UN    "DB_POWER_SAVING_MODE2".GENERAL.SM.CR_MODE_2_ON;
      UN    "ASU_CR_LOOP_C_ON";
      O     ;
      U     "DB_POWER_SAVING_MODE2".GENERAL.SM.CR_MODE_2_ON;
      UN    "DB_POWER_SAVING_MODE2".MODE.CR_ASU_HEATING;
      )     ;
      U     "LOG_0";
      O     "DB_GRP_84".FAN71.SM.GeneralError;
      O     "DB_DIGIT".FM.G84_FAN71;
      O     "DB_DIGIT".FM.G84_DOO07;
      O     "DB_DIGIT".FM.G84_MT33;
      O     "DB_DIGIT".FM.G84_MT53;
      O     "DB_GRP_80".FAN94.SM.GeneralError;
      O     "DB_DIGIT".FM.G80_FAN94_S32F;
      )     ;
      =     #AutoOff;
NETWORK
TITLE ==81PP51-U1 HEATING PUMP SETPOINT TRANSFER
//15.06.2016 Logic changed by RSZschach (EN) with acceptance from ASI
//see email from Mr.Schreiner
//
//7,0Hz minimum speed !!!
      U(    ;
      U(    ;
      U     "LOG_1";
      SPBNB _004;
      L     7.000000e+000;
      T     "DB_GRP_84".PP51.PV.Frg_SPAV_Min;
      SET   ;
      SAVE  ;
      CLR   ;
_004: U     BIE;
      )     ;
      U     "DB_GRP_84".PID_HEATING2.SM.CTRL_On;
      SPBNB _005;
      L     "DB_GRP_84".PID_HEATING2.PV.ManipulatedVariable_AV;
      T     "DB_GRP_84".PP51.PV.SP;
      SET   ;
      SAVE  ;
      CLR   ;
_005: U     BIE;
      )     ;
      NOT   ;
      U     "DB_GRP_84".PP51.SM.AutomaticMode;
      SPBNB _006;
      L     "DB_GRP_84".PP51.PV.Frg_SPAV_Min;
      T     "DB_GRP_84".PP51.PV.SP;
_006: NOP   0;
NETWORK
TITLE ==84PP51-U1 HEATING PUMP CONTROL

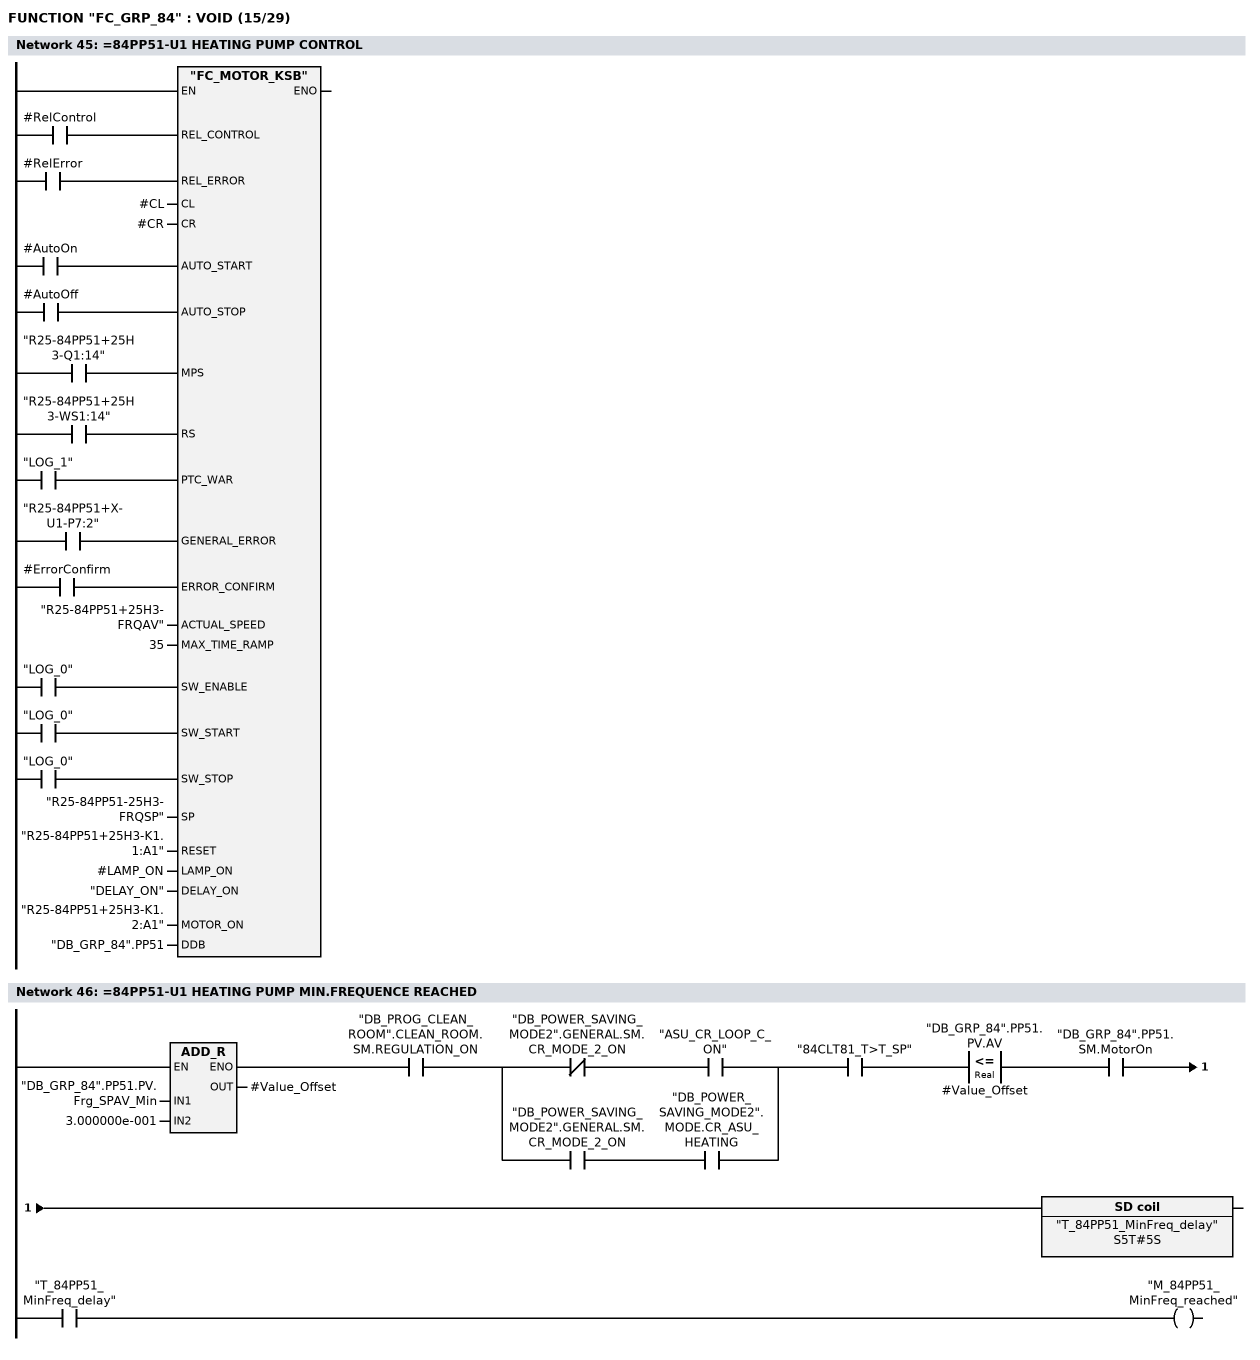
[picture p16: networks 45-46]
      U     #RelControl;
      =     L     10.0;
      BLD   103;
      U     #RelError;
      =     L     10.1;
      BLD   103;
      U     #AutoOn;
      =     L     10.2;
      BLD   103;
      U     #AutoOff;
      =     L     10.3;
      BLD   103;
      U     "R25-84PP51+25H3-Q1:14";
      =     L     10.4;
      BLD   103;
      U     "R25-84PP51+25H3-WS1:14";
      =     L     10.5;
      BLD   103;
      U     "LOG_1";
      =     L     10.6;
      BLD   103;
      U     "R25-84PP51+X-U1-P7:2";
      =     L     10.7;
      BLD   103;
      U     #ErrorConfirm;
      =     L     11.0;
      BLD   103;
      U     "LOG_0";
      =     L     11.1;
      BLD   103;
      U     "LOG_0";
      =     L     11.2;
      BLD   103;
      U     "LOG_0";
      =     L     11.3;
      BLD   103;
      CALL "FC_MOTOR_KSB" (
           REL_CONTROL              := L     10.0,
           REL_ERROR                := L     10.1,
           CL                       := #CL,
           CR                       := #CR,
           AUTO_START               := L     10.2,
           AUTO_STOP                := L     10.3,
           MPS                      := L     10.4,
           RS                       := L     10.5,
           PTC_WAR                  := L     10.6,
           GENERAL_ERROR            := L     10.7,
           ERROR_CONFIRM            := L     11.0,
           ACTUAL_SPEED             := "R25-84PP51+25H3-FRQAV",
           MAX_TIME_RAMP            := 35,
           SW_ENABLE                := L     11.1,
           SW_START                 := L     11.2,
           SW_STOP                  := L     11.3,
           SP                       := "R25-84PP51-25H3-FRQSP",
           RESET                    := "R25-84PP51+25H3-K1.1:A1",
           LAMP_ON                  := #LAMP_ON,
           DELAY_ON                 := "DELAY_ON",
           MOTOR_ON                 := "R25-84PP51+25H3-K1.2:A1",
           DDB                      := "DB_GRP_84".PP51);
      NOP   0;
NETWORK
TITLE ==84PP51-U1 HEATING PUMP MIN.FREQUENCE REACHED

      U(    ;
      L     "DB_GRP_84".PP51.PV.Frg_SPAV_Min;
      L     3.000000e-001;
      +R    ;
      T     #Value_Offset;
      UN    OV;
      SAVE  ;
      CLR   ;
      U     BIE;
      )     ;
      U     "DB_PROG_CLEAN_ROOM".CLEAN_ROOM.SM.REGULATION_ON;
      U(    ;
      UN    "DB_POWER_SAVING_MODE2".GENERAL.SM.CR_MODE_2_ON;
      U     "ASU_CR_LOOP_C_ON";
      O     ;
      U     "DB_POWER_SAVING_MODE2".GENERAL.SM.CR_MODE_2_ON;
      U     "DB_POWER_SAVING_MODE2".MODE.CR_ASU_HEATING;
      )     ;
      U     "84CLT81_T>T_SP";
      U(    ;
      L     "DB_GRP_84".PP51.PV.AV;
      L     #Value_Offset;
      <=R   ;
      )     ;
      U     "DB_GRP_84".PP51.SM.MotorOn;
      L     S5T#5S;
      SE    "T_84PP51_MinFreq_delay";
      NOP   0;
      NOP   0;
      NOP   0;
      U     "T_84PP51_MinFreq_delay";
      =     "M_84PP51_MinFreq_reached";
NETWORK
TITLE ==84VA51-M1 RELEASE CONTROL/ERROR

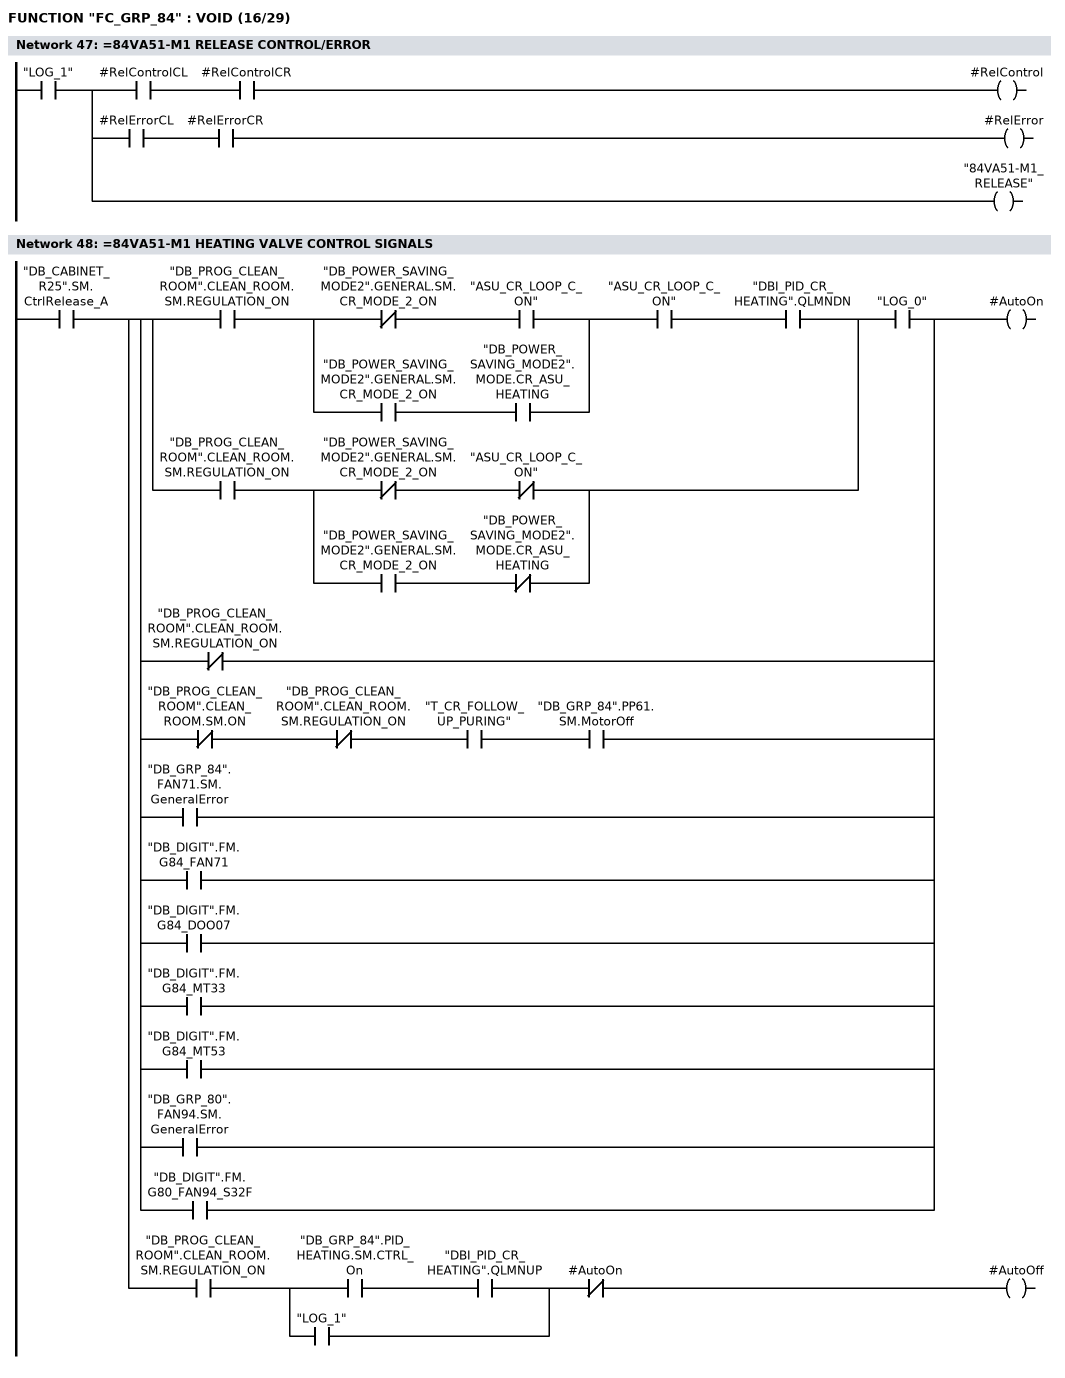
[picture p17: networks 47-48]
      U     "LOG_1";
      =     L     10.0;
      U     L     10.0;
      U     #RelControlCL;
      U     #RelControlCR;
      =     #RelControl;
      U     L     10.0;
      U     #RelErrorCL;
      U     #RelErrorCR;
      =     #RelError;
      U     L     10.0;
      BLD   102;
      =     "84VA51-M1_RELEASE";
NETWORK
TITLE ==84VA51-M1 HEATING VALVE CONTROL SIGNALS

      U     "DB_CABINET_R25".SM.CtrlRelease_A;
      =     L     10.0;
      U     L     10.0;
      U(    ;
      U(    ;
      U     "DB_PROG_CLEAN_ROOM".CLEAN_ROOM.SM.REGULATION_ON;
      U(    ;
      UN    "DB_POWER_SAVING_MODE2".GENERAL.SM.CR_MODE_2_ON;
      U     "ASU_CR_LOOP_C_ON";
      O     ;
      U     "DB_POWER_SAVING_MODE2".GENERAL.SM.CR_MODE_2_ON;
      U     "DB_POWER_SAVING_MODE2".MODE.CR_ASU_HEATING;
      )     ;
      U     "ASU_CR_LOOP_C_ON";
      U     "DBI_PID_CR_HEATING".QLMNDN;
      O     ;
      U     "DB_PROG_CLEAN_ROOM".CLEAN_ROOM.SM.REGULATION_ON;
      U(    ;
      UN    "DB_POWER_SAVING_MODE2".GENERAL.SM.CR_MODE_2_ON;
      UN    "ASU_CR_LOOP_C_ON";
      O     ;
      U     "DB_POWER_SAVING_MODE2".GENERAL.SM.CR_MODE_2_ON;
      UN    "DB_POWER_SAVING_MODE2".MODE.CR_ASU_HEATING;
      )     ;
      )     ;
      U     "LOG_0";
      ON    "DB_PROG_CLEAN_ROOM".CLEAN_ROOM.SM.REGULATION_ON;
      O     ;
      UN    "DB_PROG_CLEAN_ROOM".CLEAN_ROOM.SM.ON;
      UN    "DB_PROG_CLEAN_ROOM".CLEAN_ROOM.SM.REGULATION_ON;
      U     "T_CR_FOLLOW_UP_PURING";
      U     "DB_GRP_84".PP61.SM.MotorOff;
      O     "DB_GRP_84".FAN71.SM.GeneralError;
      O     "DB_DIGIT".FM.G84_FAN71;
      O     "DB_DIGIT".FM.G84_DOO07;
      O     "DB_DIGIT".FM.G84_MT33;
      O     "DB_DIGIT".FM.G84_MT53;
      O     "DB_GRP_80".FAN94.SM.GeneralError;
      O     "DB_DIGIT".FM.G80_FAN94_S32F;
      )     ;
      =     #AutoOn;
      U     L     10.0;
      U     "DB_PROG_CLEAN_ROOM".CLEAN_ROOM.SM.REGULATION_ON;
      U(    ;
      U     "DB_GRP_84".PID_HEATING.SM.CTRL_On;
      U     "DBI_PID_CR_HEATING".QLMNUP;
      O     "LOG_1";
      )     ;
      UN    #AutoOn;
      =     #AutoOff;
NETWORK
TITLE ==84VA51-M1 FORCE OPENING
//15.06.2016 Logic changed by RSZschach (EN) with acceptance from ASI
//see email from Mr.Schreiner
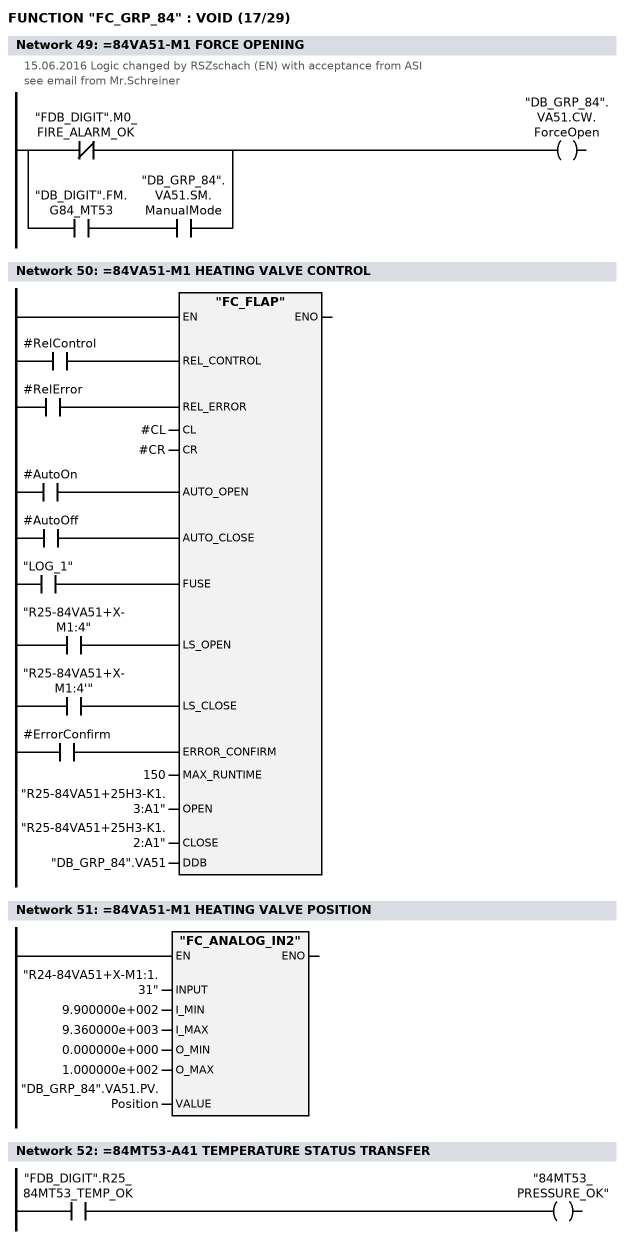
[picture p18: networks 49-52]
      ON    "FDB_DIGIT".M0_FIRE_ALARM_OK;
      O     ;
      U     "DB_DIGIT".FM.G84_MT53;
      U     "DB_GRP_84".VA51.SM.ManualMode;
      =     "DB_GRP_84".VA51.CW.ForceOpen;
NETWORK
TITLE ==84VA51-M1 HEATING VALVE CONTROL

      U     #RelControl;
      =     L     10.0;
      BLD   103;
      U     #RelError;
      =     L     10.1;
      BLD   103;
      U     #AutoOn;
      =     L     10.2;
      BLD   103;
      U     #AutoOff;
      =     L     10.3;
      BLD   103;
      U     "LOG_1";
      =     L     10.4;
      BLD   103;
      U     "R25-84VA51+X-M1:4";
      =     L     10.5;
      BLD   103;
      U     "R25-84VA51+X-M1:4'";
      =     L     10.6;
      BLD   103;
      U     #ErrorConfirm;
      =     L     10.7;
      BLD   103;
      CALL "FC_FLAP" (
           REL_CONTROL              := L     10.0,
           REL_ERROR                := L     10.1,
           CL                       := #CL,
           CR                       := #CR,
           AUTO_OPEN                := L     10.2,
           AUTO_CLOSE               := L     10.3,
           FUSE                     := L     10.4,
           LS_OPEN                  := L     10.5,
           LS_CLOSE                 := L     10.6,
           ERROR_CONFIRM            := L     10.7,
           MAX_RUNTIME              := 150,
           OPEN                     := "R25-84VA51+25H3-K1.3:A1",
           CLOSE                    := "R25-84VA51+25H3-K1.2:A1",
           DDB                      := "DB_GRP_84".VA51);
      NOP   0;
NETWORK
TITLE ==84VA51-M1 HEATING VALVE POSITION

      CALL "FC_ANALOG_IN2" (
           INPUT                    := "R24-84VA51+X-M1:1.31",
           I_MIN                    := 9.900000e+002,
           I_MAX                    := 9.360000e+003,
           O_MIN                    := 0.000000e+000,
           O_MAX                    := 1.000000e+002,
           VALUE                    := "DB_GRP_84".VA51.PV.Position);
      NOP   0;
NETWORK
TITLE ==84MT53-A41 TEMPERATURE STATUS TRANSFER

      U     "FDB_DIGIT".R25_84MT53_TEMP_OK;
      =     "84MT53_PRESSURE_OK";
NETWORK
TITLE ==84MT53-A41 TEMPERATURE PREHEATER FAULT

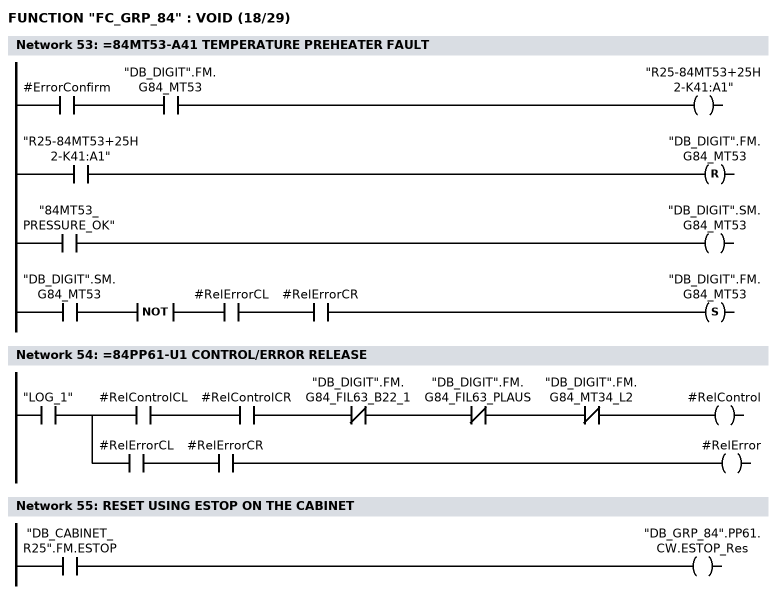
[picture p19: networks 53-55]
      U     #ErrorConfirm;
      U     "DB_DIGIT".FM.G84_MT53;
      =     "R25-84MT53+25H2-K41:A1";
      U     "R25-84MT53+25H2-K41:A1";
      R     "DB_DIGIT".FM.G84_MT53;
      U     "84MT53_PRESSURE_OK";
      =     "DB_DIGIT".SM.G84_MT53;
      U     "DB_DIGIT".SM.G84_MT53;
      NOT   ;
      U     #RelErrorCL;
      U     #RelErrorCR;
      S     "DB_DIGIT".FM.G84_MT53;
      NOP   0;
NETWORK
TITLE ==84PP61-U1 CONTROL/ERROR RELEASE

      U     "LOG_1";
      =     L     10.0;
      U     L     10.0;
      U     #RelControlCL;
      U     #RelControlCR;
      UN    "DB_DIGIT".FM.G84_FIL63_B22_1;
      UN    "DB_DIGIT".FM.G84_FIL63_PLAUS;
      UN    "DB_DIGIT".FM.G84_MT34_L2;
      =     #RelControl;
      U     L     10.0;
      U     #RelErrorCL;
      U     #RelErrorCR;
      =     #RelError;
NETWORK
TITLE =RESET USING ESTOP ON THE CABINET

      U     "DB_CABINET_R25".FM.ESTOP;
      =     "DB_GRP_84".PP61.CW.ESTOP_Res;
NETWORK
TITLE ==84PP61-U1 HUMIDIFIER PUMP

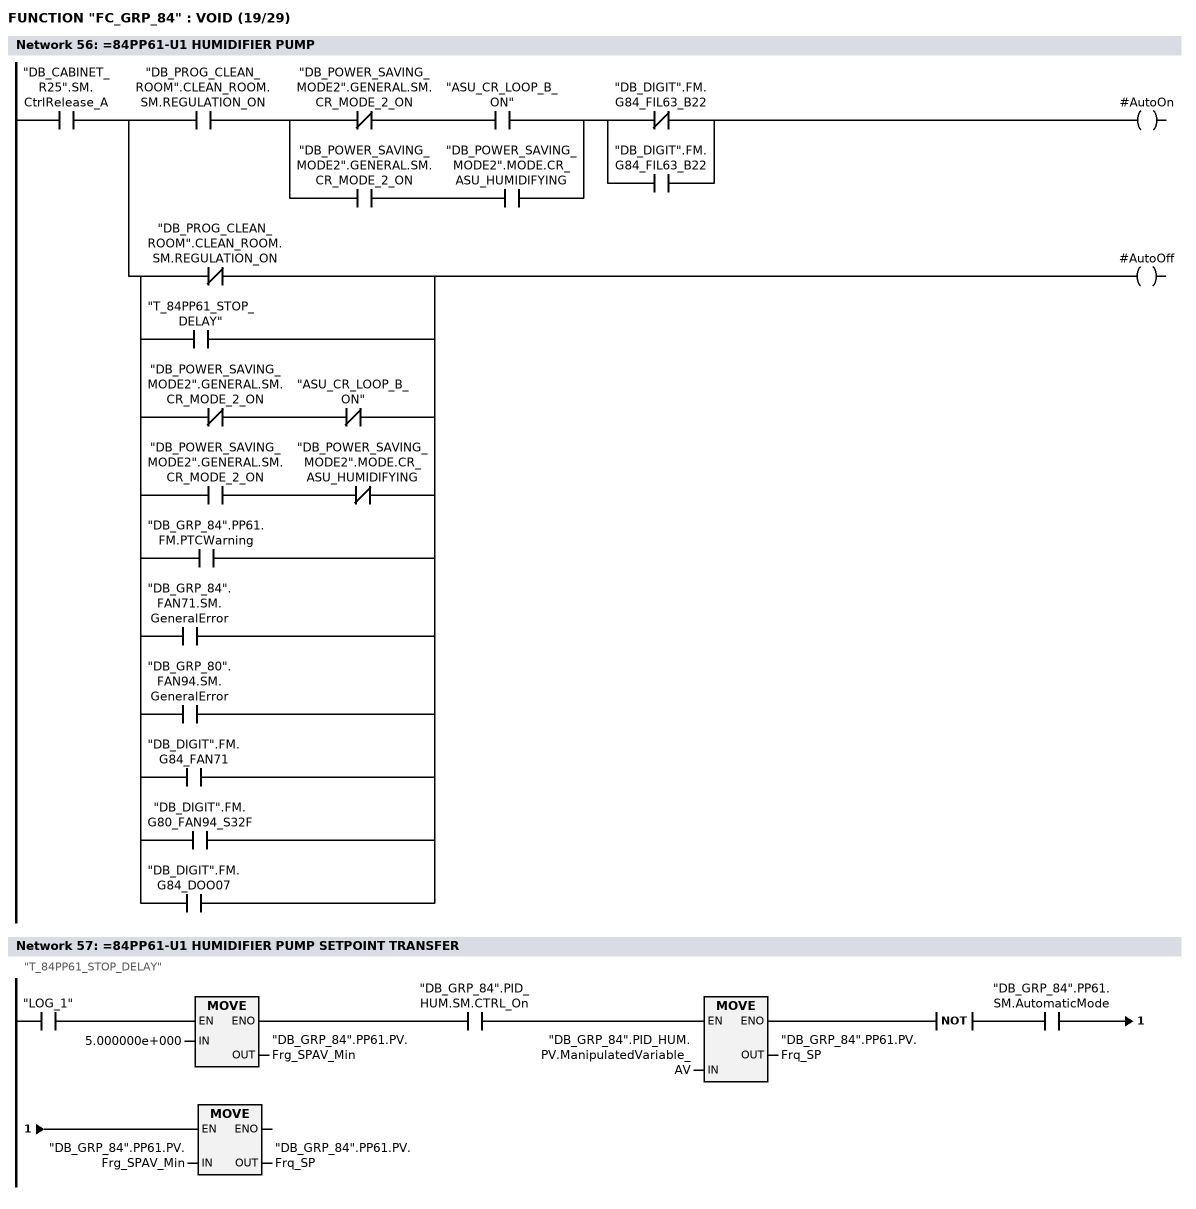
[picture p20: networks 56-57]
      U     "DB_CABINET_R25".SM.CtrlRelease_A;
      =     L     10.0;
      U     L     10.0;
      U     "DB_PROG_CLEAN_ROOM".CLEAN_ROOM.SM.REGULATION_ON;
      U(    ;
      UN    "DB_POWER_SAVING_MODE2".GENERAL.SM.CR_MODE_2_ON;
      U     "ASU_CR_LOOP_B_ON";
      O     ;
      U     "DB_POWER_SAVING_MODE2".GENERAL.SM.CR_MODE_2_ON;
      U     "DB_POWER_SAVING_MODE2".MODE.CR_ASU_HUMIDIFYING;
      )     ;
      U(    ;
      ON    "DB_DIGIT".FM.G84_FIL63_B22;
      O     "DB_DIGIT".FM.G84_FIL63_B22;
      )     ;
      =     #AutoOn;
      U     L     10.0;
      U(    ;
      ON    "DB_PROG_CLEAN_ROOM".CLEAN_ROOM.SM.REGULATION_ON;
      O     "T_84PP61_STOP_DELAY";
      O     ;
      UN    "DB_POWER_SAVING_MODE2".GENERAL.SM.CR_MODE_2_ON;
      UN    "ASU_CR_LOOP_B_ON";
      O     ;
      U     "DB_POWER_SAVING_MODE2".GENERAL.SM.CR_MODE_2_ON;
      UN    "DB_POWER_SAVING_MODE2".MODE.CR_ASU_HUMIDIFYING;
      O     "DB_GRP_84".PP61.FM.PTCWarning;
      O     "DB_GRP_84".FAN71.SM.GeneralError;
      O     "DB_GRP_80".FAN94.SM.GeneralError;
      O     "DB_DIGIT".FM.G84_FAN71;
      O     "DB_DIGIT".FM.G80_FAN94_S32F;
      O     "DB_DIGIT".FM.G84_DOO07;
      )     ;
      =     #AutoOff;
NETWORK
TITLE ==84PP61-U1 HUMIDIFIER PUMP SETPOINT TRANSFER
//"T_84PP61_STOP_DELAY"
      U(    ;
      U(    ;
      U     "LOG_1";
      SPBNB _007;
      L     5.000000e+000;
      T     "DB_GRP_84".PP61.PV.Frg_SPAV_Min;
      SET   ;
      SAVE  ;
      CLR   ;
_007: U     BIE;
      )     ;
      U     "DB_GRP_84".PID_HUM.SM.CTRL_On;
      SPBNB _008;
      L     "DB_GRP_84".PID_HUM.PV.ManipulatedVariable_AV;
      T     "DB_GRP_84".PP61.PV.Frq_SP;
      SET   ;
      SAVE  ;
      CLR   ;
_008: U     BIE;
      )     ;
      NOT   ;
      U     "DB_GRP_84".PP61.SM.AutomaticMode;
      SPBNB _009;
      L     "DB_GRP_84".PP61.PV.Frg_SPAV_Min;
      T     "DB_GRP_84".PP61.PV.Frq_SP;
_009: NOP   0;
NETWORK
TITLE ==84PP61-U1 HUMIDIFIER PUMP

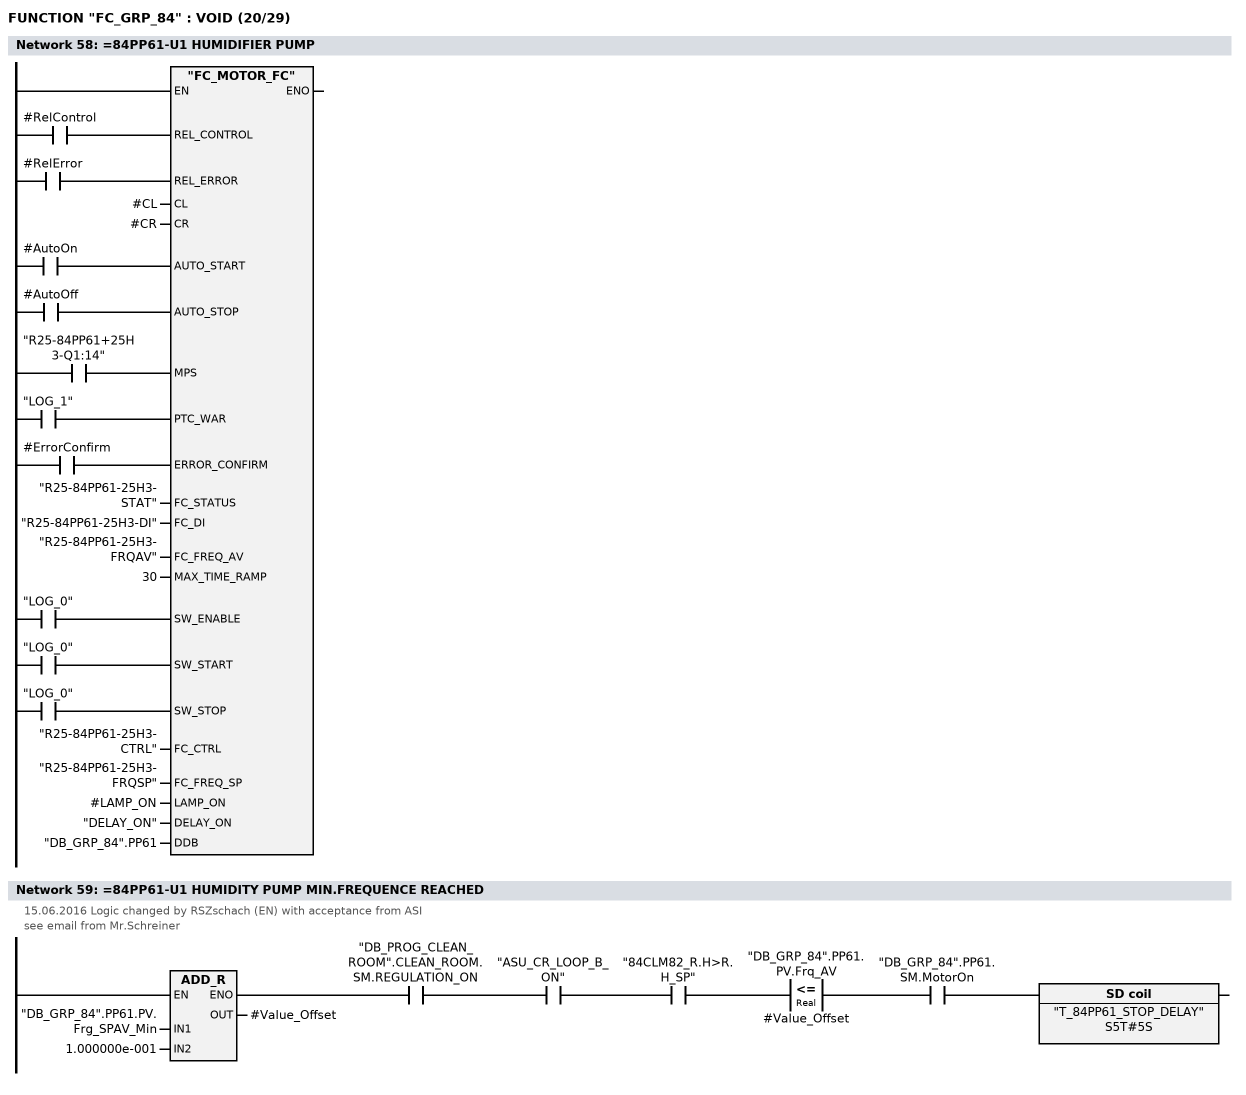
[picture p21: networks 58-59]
      U     #RelControl;
      =     L     10.0;
      BLD   103;
      U     #RelError;
      =     L     10.1;
      BLD   103;
      U     #AutoOn;
      =     L     10.2;
      BLD   103;
      U     #AutoOff;
      =     L     10.3;
      BLD   103;
      U     "R25-84PP61+25H3-Q1:14";
      =     L     10.4;
      BLD   103;
      U     "LOG_1";
      =     L     10.5;
      BLD   103;
      U     #ErrorConfirm;
      =     L     10.6;
      BLD   103;
      U     "LOG_0";
      =     L     10.7;
      BLD   103;
      U     "LOG_0";
      =     L     11.0;
      BLD   103;
      U     "LOG_0";
      =     L     11.1;
      BLD   103;
      CALL "FC_MOTOR_FC" (
           REL_CONTROL              := L     10.0,
           REL_ERROR                := L     10.1,
           CL                       := #CL,
           CR                       := #CR,
           AUTO_START               := L     10.2,
           AUTO_STOP                := L     10.3,
           MPS                      := L     10.4,
           PTC_WAR                  := L     10.5,
           ERROR_CONFIRM            := L     10.6,
           FC_STATUS                := "R25-84PP61-25H3-STAT",
           FC_DI                    := "R25-84PP61-25H3-DI",
           FC_FREQ_AV               := "R25-84PP61-25H3-FRQAV",
           MAX_TIME_RAMP            := 30,
           SW_ENABLE                := L     10.7,
           SW_START                 := L     11.0,
           SW_STOP                  := L     11.1,
           FC_CTRL                  := "R25-84PP61-25H3-CTRL",
           FC_FREQ_SP               := "R25-84PP61-25H3-FRQSP",
           LAMP_ON                  := #LAMP_ON,
           DELAY_ON                 := "DELAY_ON",
           DDB                      := "DB_GRP_84".PP61);
      NOP   0;
NETWORK
TITLE ==84PP61-U1 HUMIDITY PUMP MIN.FREQUENCE REACHED
//15.06.2016 Logic changed by RSZschach (EN) with acceptance from ASI
//see email from Mr.Schreiner
      U(    ;
      L     "DB_GRP_84".PP61.PV.Frg_SPAV_Min;
      L     1.000000e-001;
      +R    ;
      T     #Value_Offset;
      UN    OV;
      SAVE  ;
      CLR   ;
      U     BIE;
      )     ;
      U     "DB_PROG_CLEAN_ROOM".CLEAN_ROOM.SM.REGULATION_ON;
      U     "ASU_CR_LOOP_B_ON";
      U     "84CLM82_R.H>R.H_SP";
      U(    ;
      L     "DB_GRP_84".PP61.PV.Frq_AV;
      L     #Value_Offset;
      <=R   ;
      )     ;
      U     "DB_GRP_84".PP61.SM.MotorOn;
      L     S5T#5S;
      SE    "T_84PP61_STOP_DELAY";
      NOP   0;
      NOP   0;
      NOP   0;
      NOP   0;
NETWORK
TITLE ==84PP61-B85 VIBRATION MONITORING

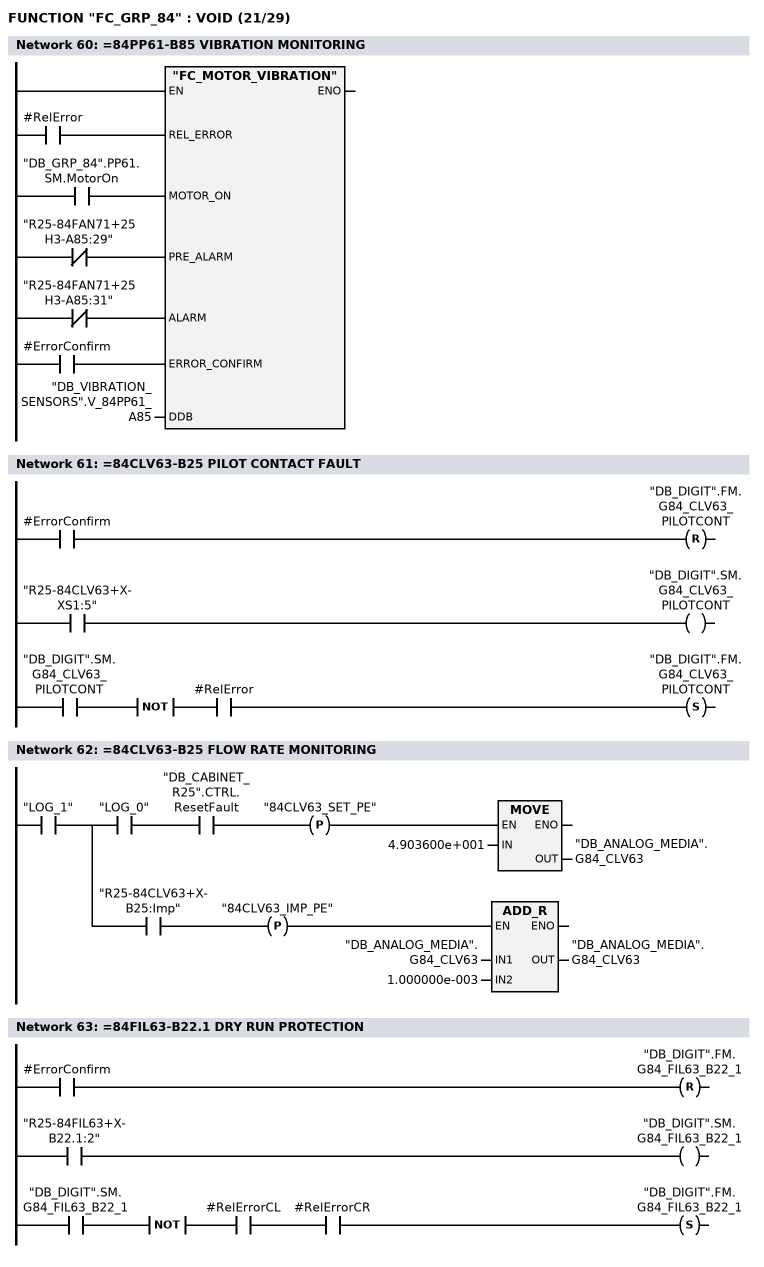
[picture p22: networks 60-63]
      U     #RelError;
      =     L     10.0;
      BLD   103;
      U     "DB_GRP_84".PP61.SM.MotorOn;
      =     L     10.1;
      BLD   103;
      UN    "R25-84FAN71+25H3-A85:29";
      =     L     10.2;
      BLD   103;
      UN    "R25-84FAN71+25H3-A85:31";
      =     L     10.3;
      BLD   103;
      U     #ErrorConfirm;
      =     L     10.4;
      BLD   103;
      CALL "FC_MOTOR_VIBRATION" (
           REL_ERROR                := L     10.0,
           MOTOR_ON                 := L     10.1,
           PRE_ALARM                := L     10.2,
           ALARM                    := L     10.3,
           ERROR_CONFIRM            := L     10.4,
           DDB                      := "DB_VIBRATION_SENSORS".V_84PP61_A85);
      NOP   0;
NETWORK
TITLE ==84CLV63-B25 PILOT CONTACT FAULT

      U     #ErrorConfirm;
      R     "DB_DIGIT".FM.G84_CLV63_PILOTCONT;
      U     "R25-84CLV63+X-XS1:5";
      =     "DB_DIGIT".SM.G84_CLV63_PILOTCONT;
      U     "DB_DIGIT".SM.G84_CLV63_PILOTCONT;
      NOT   ;
      U     #RelError;
      S     "DB_DIGIT".FM.G84_CLV63_PILOTCONT;
      NOP   0;
NETWORK
TITLE ==84CLV63-B25 FLOW RATE MONITORING

      U     "LOG_1";
      =     L     10.0;
      U     L     10.0;
      U     "LOG_0";
      U     "DB_CABINET_R25".CTRL.ResetFault;
      FP    "84CLV63_SET_PE";
      SPBNB _00a;
      L     4.903600e+001;
      T     "DB_ANALOG_MEDIA".G84_CLV63;
_00a: NOP   0;
      U     L     10.0;
      U     "R25-84CLV63+X-B25:Imp";
      FP    "84CLV63_IMP_PE";
      SPBNB _00b;
      L     "DB_ANALOG_MEDIA".G84_CLV63;
      L     1.000000e-003;
      +R    ;
      T     "DB_ANALOG_MEDIA".G84_CLV63;
_00b: NOP   0;
NETWORK
TITLE ==84FIL63-B22.1 DRY RUN PROTECTION

      U     #ErrorConfirm;
      R     "DB_DIGIT".FM.G84_FIL63_B22_1;
      U     "R25-84FIL63+X-B22.1:2";
      =     "DB_DIGIT".SM.G84_FIL63_B22_1;
      U     "DB_DIGIT".SM.G84_FIL63_B22_1;
      NOT   ;
      U     #RelErrorCL;
      U     #RelErrorCR;
      S     "DB_DIGIT".FM.G84_FIL63_B22_1;
      NOP   0;
NETWORK
TITLE ==84FIL63-B22 MIN LEVEL

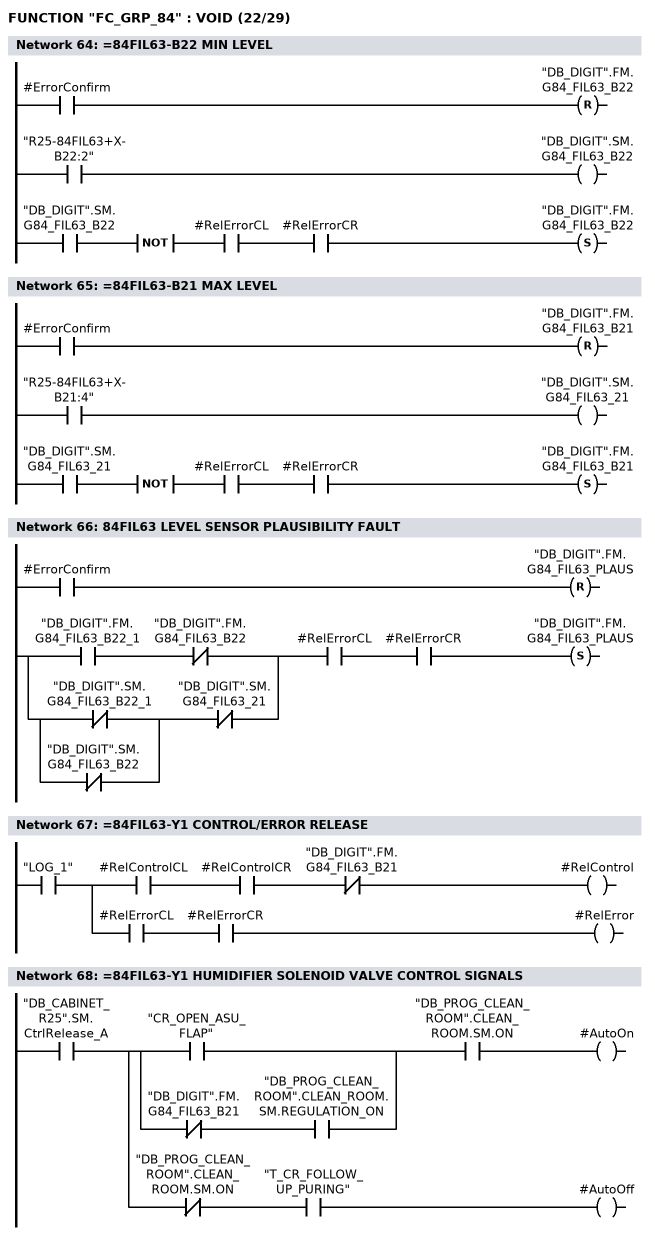
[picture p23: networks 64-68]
      U     #ErrorConfirm;
      R     "DB_DIGIT".FM.G84_FIL63_B22;
      U     "R25-84FIL63+X-B22:2";
      =     "DB_DIGIT".SM.G84_FIL63_B22;
      U     "DB_DIGIT".SM.G84_FIL63_B22;
      NOT   ;
      U     #RelErrorCL;
      U     #RelErrorCR;
      S     "DB_DIGIT".FM.G84_FIL63_B22;
      NOP   0;
NETWORK
TITLE ==84FIL63-B21 MAX LEVEL

      U     #ErrorConfirm;
      R     "DB_DIGIT".FM.G84_FIL63_B21;
      U     "R25-84FIL63+X-B21:4";
      =     "DB_DIGIT".SM.G84_FIL63_21;
      U     "DB_DIGIT".SM.G84_FIL63_21;
      NOT   ;
      U     #RelErrorCL;
      U     #RelErrorCR;
      S     "DB_DIGIT".FM.G84_FIL63_B21;
      NOP   0;
NETWORK
TITLE =84FIL63 LEVEL SENSOR PLAUSIBILITY FAULT

      U     #ErrorConfirm;
      R     "DB_DIGIT".FM.G84_FIL63_PLAUS;
      U(    ;
      U     "DB_DIGIT".FM.G84_FIL63_B22_1;
      UN    "DB_DIGIT".FM.G84_FIL63_B22;
      O     ;
      U(    ;
      ON    "DB_DIGIT".SM.G84_FIL63_B22_1;
      ON    "DB_DIGIT".SM.G84_FIL63_B22;
      )     ;
      UN    "DB_DIGIT".SM.G84_FIL63_21;
      )     ;
      U     #RelErrorCL;
      U     #RelErrorCR;
      S     "DB_DIGIT".FM.G84_FIL63_PLAUS;
      NOP   0;
NETWORK
TITLE ==84FIL63-Y1 CONTROL/ERROR RELEASE

      U     "LOG_1";
      =     L     10.0;
      U     L     10.0;
      U     #RelControlCL;
      U     #RelControlCR;
      UN    "DB_DIGIT".FM.G84_FIL63_B21;
      =     #RelControl;
      U     L     10.0;
      U     #RelErrorCL;
      U     #RelErrorCR;
      =     #RelError;
NETWORK
TITLE ==84FIL63-Y1 HUMIDIFIER SOLENOID VALVE CONTROL SIGNALS

      U     "DB_CABINET_R25".SM.CtrlRelease_A;
      =     L     10.0;
      U     L     10.0;
      U(    ;
      O     "CR_OPEN_ASU_FLAP";
      O     ;
      UN    "DB_DIGIT".FM.G84_FIL63_B21;
      U     "DB_PROG_CLEAN_ROOM".CLEAN_ROOM.SM.REGULATION_ON;
      )     ;
      U     "DB_PROG_CLEAN_ROOM".CLEAN_ROOM.SM.ON;
      =     #AutoOn;
      U     L     10.0;
      UN    "DB_PROG_CLEAN_ROOM".CLEAN_ROOM.SM.ON;
      U     "T_CR_FOLLOW_UP_PURING";
      =     #AutoOff;
NETWORK
TITLE ==84FIL63-Y1 HUMIDIFIER SOLENOID VALVE

      U     #RelControl;
      =     L     10.0;
      BLD   103;
      U     #AutoOn;
      =     L     10.1;
      BLD   103;
      U     #AutoOff;
      =     L     10.2;
      BLD   103;
      CALL "FC_VALVE" (
           REL_CONTROL              := L     10.0,
           CL                       := #CL,
           CR                       := #CR,
           AUTO_OPEN                := L     10.1,
           AUTO_CLOSE               := L     10.2,
           OPEN                     := "R25-84FIL63+X-Y1",
           DDB                      := "DB_GRP_84".FIL63_Y1);
      NOP   0;
NETWORK
TITLE ==84FTR80 FILTER PRESSURE MONITORING

      U     #RelError;
      =     L     10.0;
      BLD   103;
      U     "R25-84FTR80+X-B33-XS2:4";
      =     L     10.1;
      BLD   103;
      U     "DB_GRP_84".FAN71.SM.MotorOn;
      =     L     10.2;
      BLD   103;
      U     #ErrorConfirm;
      =     L     10.3;
      BLD   103;
      CALL "FC_ANALOG_DIGIT_MOTOR" (
           REL_ERROR                := L     10.0,
           INPUT_ANALOG             := "R25-84FTR80+X-B33-XS1:4",
           INPUT_BINARY             := L     10.1,
           I_MAX                    := 2.764800e+004,
           O_MIN                    := 0.000000e+000,
           O_MAX                    := 6.000000e+002,
           MOTOR_ON                 := L     10.2,
           MOTOR_DELAY              := 3.000000e+001,
           MAX_TIME                 := 30,
           ERROR_CONFIRM            := L     10.3,
           DDB                      := "DB_GRP_84".FTR80);
      NOP   0;
NETWORK
TITLE ==84FAN71 CONTROL/ERROR RELEASE

      U     "LOG_1";
      =     L     10.0;
      U     L     10.0;
      U     #RelControlCL;
      U     #RelControlCR;
      UN    "DB_DIGIT".FM.G84_FAN71;
      UN    "DB_DIGIT".FM.G84_DOO07;
      U     "DB_GRP_84".FLA11.SM.Open;
      UN    "DB_DIGIT".FM.G84_MT34_L2;
      =     #RelControl;
      U     L     10.0;
      U     #RelErrorCL;
      U     #RelErrorCR;
      =     #RelError;
NETWORK
TITLE ==84FAN71 START DELAY

      U     "CR_START_FANS";
      L     S5T#0MS;
      SE    "T_84FAN71_START_DELAY";
      NOP   0;
      NOP   0;
      NOP   0;
      NOP   0;
NETWORK
TITLE ==84FAN71 STOP DELAY

      U     "CR_STOP_FANS";
      L     S5T#0MS;
      SE    "T_84FAN71_STOP_DELAY";
      NOP   0;
      NOP   0;
      NOP   0;
      NOP   0;
NETWORK
TITLE ==84FAN71 SUPPLY AIR FAN CONTROL SIGNALS

      U     "DB_CABINET_R25".SM.CtrlRelease_A;
      =     L     10.0;
      U     L     10.0;
      U     "CR_START_FANS";
      U     "T_84FAN71_START_DELAY";
      =     #AutoOn;
      U     L     10.0;
      U(    ;
      U     "CR_STOP_FANS";
      U     "T_84FAN71_STOP_DELAY";
      O     "DB_GRP_84".FAN71.SM.GeneralError;
      O     "DB_GRP_80".FAN94.SM.GeneralError;
      O     "DB_DIGIT".FM.G80_FAN94_S32F;
      O     "T_80FAN94_CF";
      )     ;
      =     #AutoOff;
NETWORK
TITLE ==84FAN71-U1 SUPPLY AIR FAN ENABLE COAST DOWN

      U     "LOG_1";
      =     "DB_GRP_84".FAN71.SM.CoastDownEnabled;
NETWORK
TITLE =RESET USING ESTOP ON THE CABINET

      U     "DB_CABINET_R25".FM.ESTOP;
      =     "DB_GRP_84".FAN71.CW.ESTOP_Res;
NETWORK
TITLE =SBIT 84FAN71 RUNNING

      U     "DB_GRP_84".FAN71.SM.MotorOn;
      =     "S_84FAN71_RUNNING";
NETWORK
TITLE ==84FAN71-U1 SUPPLY AIR FAN

      U     #RelControl;
      =     L     10.0;
      BLD   103;
      U     #RelError;
      =     L     10.1;
      BLD   103;
      U     #AutoOn;
      =     L     10.2;
      BLD   103;
      U     #AutoOff;
      =     L     10.3;
      BLD   103;
      U     "R25-84FAN71+25H3-Q1:14";
      =     L     10.4;
      BLD   103;
      U     "LOG_1";
      =     L     10.5;
      BLD   103;
      U     #ErrorConfirm;
      =     L     10.6;
      BLD   103;
      U     "LOG_0";
      =     L     10.7;
      BLD   103;
      U     "LOG_0";
      =     L     11.0;
      BLD   103;
      U     "LOG_0";
      =     L     11.1;
      BLD   103;
      CALL "FC_MOTOR_FC" (
           REL_CONTROL              := L     10.0,
           REL_ERROR                := L     10.1,
           CL                       := #CL,
           CR                       := #CR,
           AUTO_START               := L     10.2,
           AUTO_STOP                := L     10.3,
           MPS                      := L     10.4,
           PTC_WAR                  := L     10.5,
           ERROR_CONFIRM            := L     10.6,
           FC_STATUS                := "R25-84FAN71-25H3-STAT",
           FC_DI                    := W#16#FFFF,
           FC_FREQ_AV               := "R25-84FAN71-25H3-FRQAV",
           MAX_TIME_RAMP            := 30,
           SW_ENABLE                := L     10.7,
           SW_START                 := L     11.0,
           SW_STOP                  := L     11.1,
           FC_CTRL                  := "R25-84FAN71-25H3-CTRL",
           FC_FREQ_SP               := "R25-84FAN71-25H3-FRQSP",
           LAMP_ON                  := #LAMP_ON,
           DELAY_ON                 := "DELAY_ON",
           DDB                      := "DB_GRP_84".FAN71);
      NOP   0;
NETWORK
TITLE ==84FAN71-U1 PRESSURE STATUS TRANSFER

      U     "FDB_DIGIT".R25_84FAN71_PRESS_OK;
      =     "84FAN71_PRESSURE_OK";
NETWORK
TITLE ==84FAN71-U1 PRESSURE MONITORING

      U     #RelError;
      =     L     10.0;
      BLD   103;
      U     "DB_GRP_84".FAN71.SM.MotorOn;
      =     L     10.1;
      BLD   103;
      U     "84FAN71_PRESSURE_OK";
      =     L     10.2;
      BLD   103;
      U     "R25-0AB59+25H1-S6:14";
      =     L     10.3;
      BLD   103;
      CALL "FC_MOTOR_PRESSURE" (
           REL_ERROR                := L     10.0,
           MOTOR_ON                 := L     10.1,
           PRESSURE                 := L     10.2,
           TIME_ON                  := 30,
           TIME_OFF                 := 85,
           ERROR_CONFIRM            := L     10.3,
           FM_PRESSURE              := "PRESS_84FAN71_ERROR",
           SM_PRESSURE              := "DB_DIGIT".SM.G84_FAN71,
           TIMER_PRESSURE           := "DB_GRP_84".FAN71.PV.PressureTimer);
      NOP   0;
NETWORK
TITLE =PRESSURE ERROR 84FAN71

      U     "R25-0AB59+25H1-S6:14";
      R     "DB_DIGIT".FM.G84_FAN71;
      U(    ;
      O     "PRESS_84FAN71_ERROR";
      O     "FDB_DIGIT".PRES_84FAN71_ERROR;
      )     ;
      U     #RelError;
      S     "DB_DIGIT".FM.G84_FAN71;
      NOP   0;
NETWORK
TITLE ==84FAN71-B85 VIBRATION MONITORING

      U     #RelError;
      =     L     10.0;
      BLD   103;
      U     "DB_GRP_84".FAN71.SM.MotorOn;
      =     L     10.1;
      BLD   103;
      UN    "R25-84FAN71+25H3-A85:25";
      =     L     10.2;
      BLD   103;
      UN    "R25-84FAN71+25H3-A85:27";
      =     L     10.3;
      BLD   103;
      U     #ErrorConfirm;
      =     L     10.4;
      BLD   103;
      CALL "FC_MOTOR_VIBRATION" (
           REL_ERROR                := L     10.0,
           MOTOR_ON                 := L     10.1,
           PRE_ALARM                := L     10.2,
           ALARM                    := L     10.3,
           ERROR_CONFIRM            := L     10.4,
           DDB                      := "DB_VIBRATION_SENSORS".V_84FAN71_A85);
      NOP   0;
NETWORK
TITLE =FORCE 84CLT81-B40N ERR. REL. IF WINDOW IS NOT REACHED AFTER TIME

      U     #RelErrorCL;
      U     #RelErrorCR;
      U     "DB_PROG_CLEAN_ROOM".CLEAN_ROOM.SM.REGULATION_ON;
      U(    ;
      U     "DB_PROG_CLEAN_ROOM".CLEAN_ROOM.SM.ON;
      U     "T_CR_PREPURING";
      O     ;
      UN    "DB_PROG_CLEAN_ROOM".CLEAN_ROOM.SM.ON;
      U     "DB_PROG_CLEAN_ROOM".CLEAN_ROOM.SM.STOP;
      )     ;
      U     "T_84CLT81_ERR_REL_DEL";
      L     S5T#1H;
      SE    "T_84CLT81_REL_ERR_FORCE";
      NOP   0;
      NOP   0;
      NOP   0;
      NOP   0;
NETWORK
TITLE ==84CLT81-B40N SETPOINT CHANGED

      U(    ;
      L     "DB_GRP_84".CLT81.PV.SP_AV;
      L     "DB_SETPOINTS".TEMP_84CLT81_SP_PREV;
      ==R   ;
      )     ;
      L     S5T#4M;
      SE    "T_84CLT81_ERR_REL_DEL";
      U(    ;
      L     "DB_GRP_84".CLT81.PV.SP_AV;
      L     "DB_SETPOINTS".TEMP_84CLT81_SP_PREV;
      <>R   ;
      )     ;
      R     "T_84CLT81_ERR_REL_DEL";
      NOP   0;
      NOP   0;
      NOP   0;
NETWORK
TITLE ==84CLT81-B40N TEMPERATURE MONITORING

      U     #RelErrorCL;
      U     #RelErrorCR;
      U     "DB_PROG_CLEAN_ROOM".CLEAN_ROOM.SM.REGULATION_ON;
      U(    ;
      U     "DB_PROG_CLEAN_ROOM".CLEAN_ROOM.SM.ON;
      U     "T_CR_PREPURING";
      O     ;
      UN    "DB_PROG_CLEAN_ROOM".CLEAN_ROOM.SM.ON;
      U     "DB_PROG_CLEAN_ROOM".CLEAN_ROOM.SM.STOP;
      )     ;
      U     "T_84CLT81_ERR_REL_DEL";
      U(    ;
      O(    ;
      L     "DB_GRP_84".CLT81.PV.AV;
      L     "DB_GRP_84".CLT81.PV.Limit_01;
      >R    ;
      )     ;
      O     "T_84CLT81_REL_ERR_FORCE";
      O     "84CLT81_REL_ERROR";
      )     ;
      =     "84CLT81_REL_ERROR";
      U     "84CLT81_REL_ERROR";
      =     L     10.0;
      BLD   103;
      U     #ErrorConfirm;
      =     L     10.1;
      BLD   103;
      CALL "FC_TEMP_HEATER2" (
           REL_ERROR                := L     10.0,
           ERROR_CONFIRM            := L     10.1,
           INPUT                    := "R25-84CLT81+X-B40N:-",
           I_MAX                    := 2.764800e+004,
           O_MIN                    := -3.000000e+001,
           O_MAX                    := 6.000000e+001,
           SETPOINT                 := "DB_GRP_84".CLT81.PV.SP_AV,
           MAX_TIME                 := 600,
           WAR_LIMIT                := 1.500000e+000,
           ERR_LIMIT                := 3.000000e+000,
           DDB                      := "DB_GRP_84".CLT81);
      NOP   0;
NETWORK
TITLE =CURRENT SETPOINT TO PREVIOUS SETPOINT

      L     "DB_GRP_84".CLT81.PV.SP_AV;
      T     "DB_SETPOINTS".TEMP_84CLT81_SP_PREV;
      NOP   0;
NETWORK
TITLE =FORCE 84CLM82-B49N ERR. REL. IF WINDOW IS NOT REACHED AFTER TIME

      U     #RelErrorCL;
      U     #RelErrorCR;
      U     "DB_PROG_CLEAN_ROOM".CLEAN_ROOM.SM.REGULATION_ON;
      U(    ;
      U     "DB_PROG_CLEAN_ROOM".CLEAN_ROOM.SM.ON;
      U     "T_CR_PREPURING";
      O     ;
      UN    "DB_PROG_CLEAN_ROOM".CLEAN_ROOM.SM.ON;
      U     "DB_PROG_CLEAN_ROOM".CLEAN_ROOM.SM.STOP;
      )     ;
      U     "T_84CLM82_ERR_REL_DEL";
      L     S5T#1H;
      SE    "T_84CLM82_REL_ERR_FORCE";
      NOP   0;
      NOP   0;
      NOP   0;
      NOP   0;
NETWORK
TITLE ==84CLM82-B49N SETPOINT CHANGED

      U(    ;
      L     "DB_GRP_84".CLM82_HUM.PV.SP_AV;
      L     "DB_SETPOINTS".HUM_84CLM82_SP_PREV;
      ==R   ;
      )     ;
      L     S5T#4M;
      SE    "T_84CLM82_ERR_REL_DEL";
      U(    ;
      L     "DB_GRP_84".CLM82_HUM.PV.SP_AV;
      L     "DB_SETPOINTS".HUM_84CLM82_SP_PREV;
      <>R   ;
      )     ;
      R     "T_84CLM82_ERR_REL_DEL";
      NOP   0;
      NOP   0;
      NOP   0;
NETWORK
TITLE ==84CLM82-B49N HUMIDITY MONITORING

      U     #RelErrorCL;
      U     #RelErrorCR;
      U     "DB_PROG_CLEAN_ROOM".CLEAN_ROOM.SM.REGULATION_ON;
      U(    ;
      U     "DB_PROG_CLEAN_ROOM".CLEAN_ROOM.SM.ON;
      U     "T_CR_PREPURING";
      O     ;
      UN    "DB_PROG_CLEAN_ROOM".CLEAN_ROOM.SM.ON;
      U     "DB_PROG_CLEAN_ROOM".CLEAN_ROOM.SM.STOP;
      )     ;
      U     "T_84CLM82_ERR_REL_DEL";
      U(    ;
      U(    ;
      L     "DB_GRP_84".CLM82_HUM.PV.AV;
      L     "DB_GRP_84".CLM82_HUM.PV.Limit_01;
      >R    ;
      )     ;
      U(    ;
      L     "DB_GRP_84".CLM82_HUM.PV.AV;
      L     "DB_GRP_84".CLM82_HUM.PV.Limit_04;
      <R    ;
      )     ;
      O     "T_84CLM82_REL_ERR_FORCE";
      O     "84CLM82_HUM_REL_ERROR";
      )     ;
      =     "84CLM82_HUM_REL_ERROR";
      U     "84CLM82_HUM_REL_ERROR";
      =     L     10.0;
      BLD   103;
      U     #ErrorConfirm;
      =     L     10.1;
      BLD   103;
      CALL "FC_TEMP_HEATER2" (
           REL_ERROR                := L     10.0,
           ERROR_CONFIRM            := L     10.1,
           INPUT                    := "R25-84CLM82+X-B49N:2",
           I_MAX                    := 2.764800e+004,
           O_MIN                    := 0.000000e+000,
           O_MAX                    := 1.000000e+002,
           SETPOINT                 := "DB_GRP_84".CLM82_HUM.PV.SP_AV,
           MAX_TIME                 := 600,
           WAR_LIMIT                := 6.000000e+000,
           ERR_LIMIT                := 1.000000e+001,
           DDB                      := "DB_GRP_84".CLM82_HUM);
      NOP   0;
NETWORK
TITLE =CURRENT SETPOINT TO PREVIOUS SETPOINT

      L     "DB_GRP_84".CLM82_HUM.PV.SP_AV;
      T     "DB_SETPOINTS".HUM_84CLM82_SP_PREV;
      NOP   0;
NETWORK
TITLE ==84CLM82-B49N TEMPERATURE MONITORING
//IN PAP THERE IS INFORMATION THAT THIS TEMPERATURE SENSOR IS NOT USED (THERE IS
//ONE DEVICE MEASURING HUMIDITY AND TEMPERATURE)
      U     #RelErrorCL;
      U     #RelErrorCR;
      U     "DB_PROG_CLEAN_ROOM".CLEAN_ROOM.SM.REGULATION_ON;
      U     "DB_PROG_CLEAN_ROOM".CLEAN_ROOM.SM.ON;
      U     "T_CR_PREPURING";
      U(    ;
      O(    ;
      L     "DB_GRP_84".CLM82_TEMP.PV.AV;
      L     "DB_GRP_84".CLM82_TEMP.PV.Limit_01;
      >R    ;
      )     ;
      O     "84CLM82_TEMP_REL_ERROR";
      )     ;
      =     "84CLM82_TEMP_REL_ERROR";
      U     "84CLM82_TEMP_REL_ERROR";
      U     "LOG_0";
      =     L     10.0;
      BLD   103;
      U     #ErrorConfirm;
      =     L     10.1;
      BLD   103;
      CALL "FC_TEMP_HEATER2" (
           REL_ERROR                := L     10.0,
           ERROR_CONFIRM            := L     10.1,
           INPUT                    := "R25-84CLM82+X-B49N:5",
           I_MAX                    := 2.764800e+004,
           O_MIN                    := -2.000000e+001,
           O_MAX                    := 8.000000e+001,
           SETPOINT                 := "DB_GRP_84".CLM82_TEMP.PV.SP_AV,
           MAX_TIME                 := 30,
           WAR_LIMIT                := 1.500000e+000,
           ERR_LIMIT                := 3.000000e+000,
           DDB                      := "DB_GRP_84".CLM82_TEMP);
      NOP   0;
NETWORK
TITLE =END



END_FUNCTION

